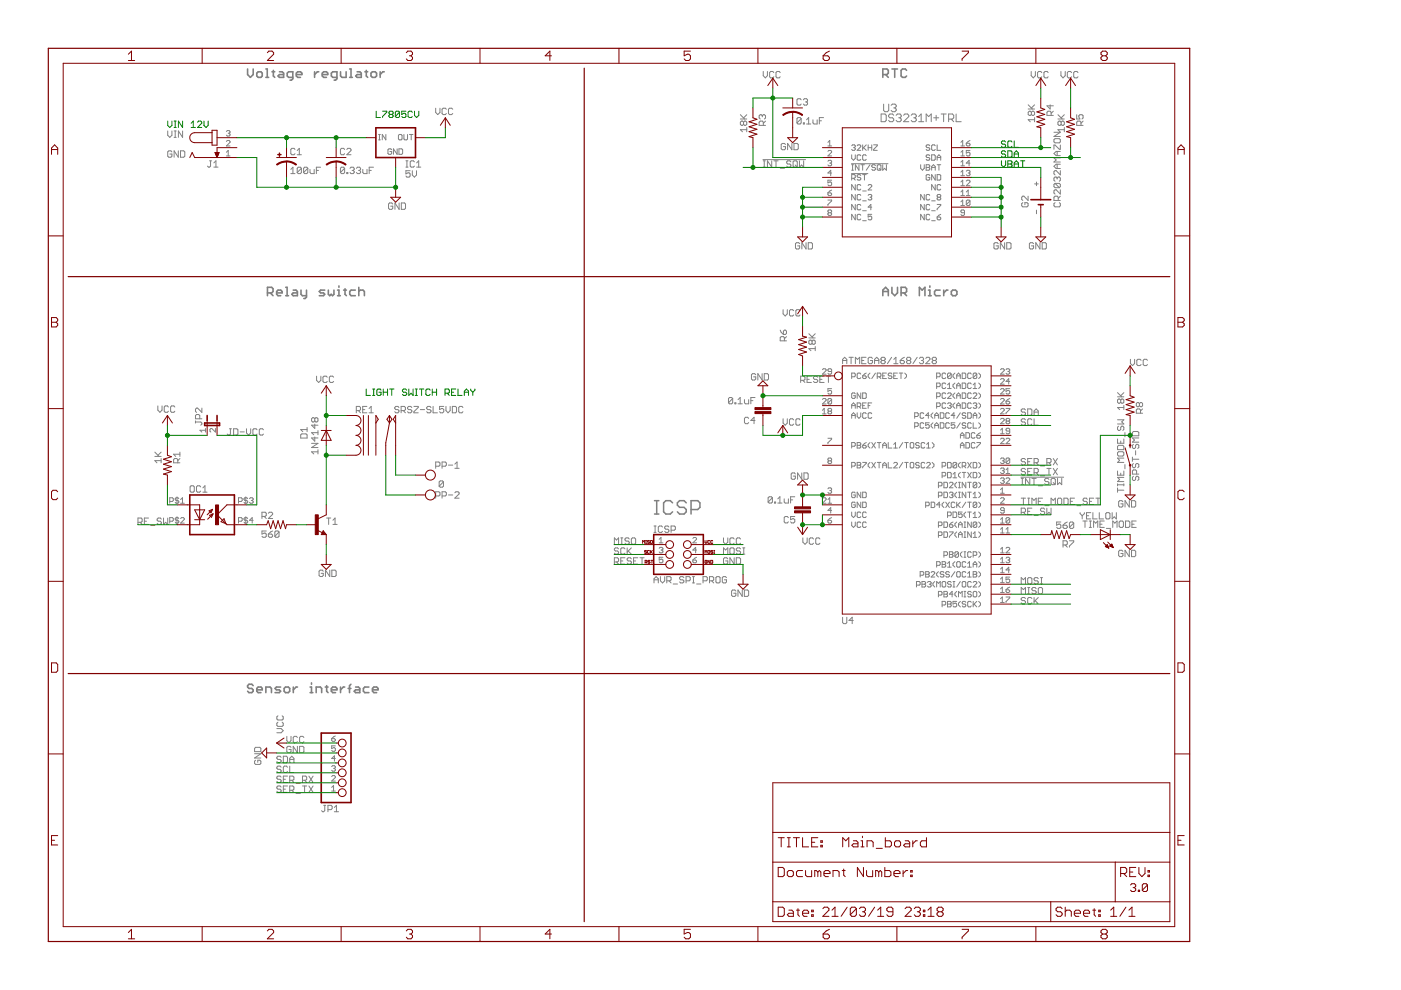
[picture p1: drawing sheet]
<svg xmlns="http://www.w3.org/2000/svg" width="297mm" height="210mm" viewBox="0 0 297 210" stroke-linecap="round" stroke-linejoin="round" font-family="sans-serif">
<g fill="none" stroke="#808080" stroke-width=".34">
<path d="M52.5 14.6v1.2l.6 .6 .6-.6v-1.2M54.4 15.5l.3-.3h.6l.3 .3v.6l-.3 .3h-.6l-.3-.3zM56.4 14.6h.3v1.8M56.4 16.4h.6M57.7 15.2h.6M58 14.9v1.2l.3 .3M59.2 15.2h.6l.3 .3v.9h-.9l-.3-.3 .3-.3h.9M62.1 16.4h-.9l-.3-.3v-.6l.3-.3h.9v1.5l-.3 .3h-.3M62.8 15.8h1.2v-.3l-.3-.3h-.6l-.3 .3v.6l.3 .3h.6M66.7 15.2v1.2M67.6 15.2h-.3l-.6 .6M68.3 15.8h1.2v-.3l-.3-.3h-.6l-.3 .3v.6l.3 .3h.6"/>
<path d="M71.4 16.4h-.9l-.2-.3v-.6l.2-.3h.9v1.5l-.3 .3h-.3M72.2 15.2v.9l.3 .3h.9v-1.2M74.1 14.6h.3v1.8M74.1 16.4h.6M75.7 15.2h.6l.3 .3v.9h-.9l-.3-.3 .3-.3h.9M77.4 15.2h.6M77.7 14.9v1.2l.3 .3M78.7 15.5l.3-.3h.5l.3 .3v.6l-.3 .3h-.5l-.3-.3zM80.6 15.2v1.2M81.5 15.2h-.3l-.6 .6M187.2 15.8h.8l.3-.3v-.6l-.3-.3h-.8v1.8M187.8 15.8l.5 .6"/>
<path d="M189.1 14.6h1.2M189.7 14.6v1.8M192.2 14.9l-.3-.3h-.6l-.2 .3v1.2l.2 .3h.6l.3-.3M56.7 62.1h.9l.3-.3v-.6l-.3-.3h-.9v1.8M57.3 62.1l.6 .6M58.7 62.1h1.1v-.3l-.3-.3h-.6l-.2 .3v.6l.2 .3h.6M60.6 60.9h.3v1.8M60.6 62.7h.6M62.2 61.5h.6l.3 .3v.9h-.9l-.3-.3 .3-.3h.9M63.8 61.5v.9l.3 .3h.9M65 61.5v1.5l-.3 .3h-.3M68.9 61.5h-.9l-.3 .3 .3 .3h.6l.3 .3-.3 .3h-.9"/>
<path d="M69.6 61.5v.9l.3 .3 .3-.3 .3 .3 .3-.3v-.9M71.6 61.5h.3v1.2M71.6 62.7h.6M71.9 60.6v.3M72.9 61.5h.5M73.2 61.2v1.2l.2 .3M75.3 61.5h-.9l-.3 .3v.6l.3 .3h.9M76.1 61.8l.3-.3h.6l.3 .3v.9M76.1 60.9v1.8M187.2 62.7v-1.2l.6-.6 .5 .6v1.2M187.2 61.8h1.1M189.1 60.9v1.2l.6 .6 .6-.6v-1.2"/>
<path d="M191.1 62.1h.8l.3-.3v-.6l-.3-.3h-.8v1.8M191.6 62.1l.6 .6M194.9 62.7v-1.8l.6 .6 .6-.6v1.8M196.8 61.5h.3v1.2M196.8 62.7h.6M197.1 60.6v.3M199.3 61.5h-.9l-.3 .3v.6l.3 .3h.9M200.1 61.5v1.2M201 61.5h-.3l-.6 .6M202 61.5h.6l.3 .3v.6l-.3 .3h-.6l-.3-.3v-.6zM53.7 145.4l-.3-.3h-.6l-.3 .3v.3l.3 .3h.6l.3 .3v.3l-.3 .3h-.6l-.3-.3M54.4 146.3h1.2v-.3l-.3-.3h-.6l-.3 .3v.6l.3 .3h.6"/>
<path d="M56.4 146.9v-1.2h.9l.3 .3v.9M59.5 145.7h-.9l-.3 .3 .3 .3h.6l.3 .3-.3 .3h-.9M60.2 146l.3-.3h.6l.3 .3v.6l-.3 .3h-.6l-.3-.3zM62.2 145.7v1.2M63.1 145.7h-.3l-.6 .6M65.7 146.9h.6M65.7 145.7h.3v1.2M66 144.8v.3M67 146.9v-1.2h.9l.3 .3v.9M69 145.7h.6M69.3 145.4v1.2l.3 .3M70.3 146.3h1.1v-.3l-.3-.3h-.6l-.2 .3v.6l.2 .3h.6"/>
<path d="M72.2 145.7v1.2M73.1 145.7h-.3l-.6 .6M73.8 146h.6M74.4 145.1l-.3 .3v1.5M75.4 145.7h.6l.3 .3v.9h-.9l-.3-.3 .3-.3h.9M78.2 145.7h-.9l-.3 .3v.6l.3 .3h.9M79 146.3h1.2v-.3l-.3-.3h-.6l-.3 .3v.6l.3 .3h.6"/>
</g>
<path d="M138.8 109h.9M138.8 106.2h.9M139.2 106.2v2.8M142.6 106.6l-.5-.4h-.9l-.5 .4v1.9l.5 .5h.9l.5-.5M145.5 106.6l-.5-.4h-.9l-.5 .4v.5l.5 .5h.9l.5 .4v.5l-.5 .5h-.9l-.5-.5M146.5 108h1.4l.5-.4v-1l-.5-.4h-1.4v2.8" fill="none" stroke="#808080" stroke-width=".32"/>
<g fill="none" stroke="#808080" stroke-width=".21">
<path d="M161.8 15.2v.8l.5 .5 .4-.5v-.8M164.1 15.4l-.2-.2h-.5l-.2 .2v.9l.2 .2h.5l.2-.2M165.4 15.4l-.2-.2h-.5l-.2 .2v.9l.2 .2h.5l.2-.2M218.6 15.2v.8l.5 .5 .4-.5v-.8M220.9 15.4l-.2-.2h-.5l-.2 .2v.9l.2 .2h.5l.2-.2M222.2 15.4l-.2-.2h-.4l-.3 .2v.9l.3 .2h.4l.2-.2M224.9 15.2v.8l.5 .5 .4-.5v-.8M227.2 15.4l-.2-.2h-.5l-.2 .2v.9l.2 .2h.5l.2-.2M228.6 15.4l-.3-.2h-.4l-.3 .2v.9l.3 .2h.4l.3-.2M35.6 27.8v.9l.4 .4 .4-.4v-.9M36.4 32.2l-.2-.2h-.4l-.2 .2v.9l.2 .2h.4l.2-.2v-.4h-.4M36.9 29.1h.5"/>
<path d="M36.9 27.8h.5M37.1 27.8v1.3M37.8 32v1.3l-.9-1.3v1.3M38.3 32h.6l.3 .2v.9l-.3 .2h-.6zM38.7 27.8v1.3l-.9-1.3v1.3M44.4 34.1h.5M44.6 34.1v1.1l-.2 .2-.4-.2M45.3 35.4h.9M45.3 34.5l.5-.4v1.3M48 30l.2-.2h.4l.2 .2v.2l-.8 .7h.8M48 33.1h.8M48 27.9l.2-.2h.4l.2 .2-.2 .4"/>
<path d="M48 32.3l.4-.4v1.2M48.4 28.3h.2M48.6 28.3l.2 .1-.2 .5h-.4l-.2-.2M61.7 36.8h.8M61.7 35.9l.4-.4v1.3M62.5 31.7l-.2-.2h-.4l-.2 .2v.9l.2 .2h.4l.2-.2M63 32.8h.9M63 31.9l.5-.4v1.3M63.9 35.7l-.2-.2h-.5l-.2 .2v.9M63.9 35.7v.9l-.2 .2h-.5l-.2-.2M63.9 35.7l-.9 .9M65.3 35.7l-.3-.2h-.4l-.2 .2v.9"/>
<path d="M65.3 35.7v.9l-.3 .2h-.4l-.2-.2M65.3 35.7l-.9 .9M65.7 35.9v.7l.3 .2h.6v-.9M67.1 36.1h.4M68 35.5h-.9v1.3M73.1 31.7l-.2-.2h-.5l-.2 .2v.9l.2 .2h.5l.2-.2M73.1 35.7l-.2-.2h-.5l-.2 .2v.9M73.1 35.7v.9l-.2 .2h-.5l-.2-.2M73.1 35.7l-.9 .9M73.5 36.6h.2v.2h-.2zM73.5 31.7l.2-.2h.5l.2 .2v.2l-.9 .9h.9M74.2 35.7l.2-.2h.5l.2 .2-.2 .4"/>
<path d="M74.7 36.1h.2M74.9 36.1l.2 .3-.2 .4h-.5l-.2-.2M75.6 35.7l.2-.2h.4l.3 .2-.3 .4M76 36.1h.2M76.2 36.1l.3 .3-.3 .4h-.4l-.2-.2M76.9 35.9v.7l.3 .2h.6v-.9M78.3 36.1h.4M79.2 35.5h-.9v1.3M80.3 29.7h.3M80.3 28.5h.3M80.5 28.5v1.2M81.8 28.5v1.2l-.8-1.2v1.2"/>
<path d="M83 31.7l-.2-.1h-.3l-.2 .1v.8l.2 .2h.3l.2-.2v-.4h-.3M84.2 31.6v1.1l-.8-1.1v1.1M84.6 31.6h.6l.2 .1v.8l-.2 .2h-.6zM84.7 28.5h.3l.2 .2v.8l-.2 .2h-.3l-.2-.2v-.8zM85.6 28.5v1l.2 .2h.4l.2-.2v-1M86.1 35.4h.4M86.1 34.1h.4M86.3 34.1v1.3M86.8 28.5h.8M87 36.2h-.9v.7l.4-.3h.2l.3 .3v.4l-.3 .2h-.4l-.2-.2M87.2 28.5v1.2M87.4 36.2v.9l.5 .4 .4-.4v-.9"/>
<path d="M87.9 34.3l-.3-.2h-.4l-.2 .2v.9l.2 .2h.4l.3-.2M88.3 35.4h.9M88.3 34.5l.5-.4v1.3M92.4 22.9v.9l.4 .5 .5-.5v-.9M94.6 23.2l-.2-.3h-.4l-.3 .3v.9l.3 .2h.4l.2-.2M96 23.2l-.2-.3h-.5l-.2 .3v.9l.2 .2h.5l.2-.2M157 25.2h1.3M157 24.3l.9 .9M157.6 25.9l-.2-.2-.4 .2v.5l.2 .2 .4-.2M157.6 25.9l.3-.2 .4 .2v.5l-.2 .2h-.2l-.3-.2M157.6 25.9v.5M158.3 27.5h-1.3l.4 .4"/>
<path d="M158.3 27v.9M158.3 24.3l-.7 .7M161.6 24.6v.2M161.6 24.6l-.2-.3-.4 .3v.4l.2 .2M161.6 24.6l.2-.3 .5 .3v.4l-.2 .2M161.8 33.8h9M161.8 35.4h.5M161.8 34.1h.5M161.8 26.6v-.7l-.2-.2h-.4l-.2 .2v.7h1.3M162 34.1v1.3M162.3 25.7l-.5 .4M163.6 34.1v1.3l-.9-1.3v1.3"/>
<path d="M164.1 34.1h.9M164.5 34.1v1.3M165.4 35.7h.9M166.5 30.6l-.2-.2h-.4l-.3 .2v.9l.3 .2h.4l.2-.2v-.4h-.4M167.7 34.3l-.2-.2h-.5l-.2 .2 .2 .5h.5l.2 .4-.2 .2h-.5l-.2-.2M167.9 30.4v1.3l-.9-1.3v1.3M168.1 34.3l.3-.2h.4l.2 .2v.9l-.2 .2h-.4l-.3-.2zM168.3 30.4h.7l.2 .2v.9l-.2 .2h-.7zM168.6 35l.4 .4M169.5 34.1v1.3l.4-.4 .5 .4v-1.3M169.9 21.2l-.2-.3h-.5l-.2 .3v.9l.2 .2h.5l.2-.2M169.9 25.2l-.2-.3h-.5l-.2 .3v.9"/>
<path d="M169.9 25.2v.9l-.2 .2h-.5l-.2-.2M169.9 25.2l-.9 .9M170.3 26.1h.2v.2h-.2zM170.3 21.2l.2-.3h.5l.2 .3-.2 .4M170.8 21.6h.2M171 25.4l.4-.5v1.4M171 26.3h.9M171 21.6l.2 .2-.2 .5h-.5l-.2-.2M172.4 25.4v.7l.2 .2h.6v-.9M173.7 25.6h.5M174.6 24.9h-.9v1.4M175.5 30.2l.4-.4v1.1"/>
<path d="M175.5 30.9h.8M175.5 34.2l.2-.2h.4l.2 .2-.2 .4M175.5 32.1l.2-.2h.4l.2 .2v.2l-.8 .8h.8M175.9 34.6h.2M176.1 34.6l.2 .2-.2 .4h-.4l-.2-.2M176.3 38.2h-.8v.6l.4-.2 .4 .2v.4l-.2 .2h-.4l-.2-.2M176.3 36.7h-.8l.6-.6v1.2M180.5 36.8h3.5M180.5 34.7h7.8M180.6 32.8v.8l.4 .4 .3-.4v-.8M180.6 30.9l.2-.2h.3l.2 .2-.2 .4M180.6 37.8h.5l.2-.2v-.4l-.2-.2h-.5v1.2"/>
<path d="M180.6 36.1h.4M180.6 34.9h.4M180.8 34.9v1.2M181 31.3h.1M181 37.8l.3 .4M181.1 31.3l.2 .2-.2 .4h-.3l-.2-.2M181.3 39.1v1.2l-.7-1.2v1.2M181.7 30.9l.2-.2h.4l.2 .2v.2l-.8 .8h.8M182.1 34.9v1.2l-.7-1.2v1.2M182.5 33l-.2-.2h-.4l-.2 .2v.8l.2 .2h.4l.2-.2M182.5 37.2l-.2-.2h-.4l-.2 .2 .2 .4h.4l.2 .2-.2 .4h-.4l-.2-.2M182.5 39.3l-.2-.2h-.4l-.2 .2v.8l.2 .2h.4l.2-.2"/>
<path d="M182.5 34.9h.8M182.9 30.7v1.2M182.9 34.9v1.2M182.9 37h.8M183.1 31.3l.6 .6M183.3 37v1.2M183.7 33l-.2-.2h-.4l-.2 .2v.8l.2 .2h.4l.2-.2M183.7 30.7l-.8 .8M184.1 30.7v1.2M184.1 31.3h.7M184.1 39.3l.2-.2h.3l.2 .2v.2l-.7 .8h.7M184.4 34.9l-.7 1.2"/>
<path d="M184.8 30.7v1.2M185.2 30.7h.8l-.8 1.2h.8M185.6 35.1l-.2-.2h-.4l-.2 .2 .2 .4h.4l.2 .2-.2 .4h-.4l-.2-.2M186 35.1l.2-.2h.4l.2 .2v.8l-.2 .2h-.4l-.2-.2zM186.4 35.7l.4 .4M186.8 24.2h.8l.3 .2v1.1l-.3 .3h-.8zM187.2 34.9v1.2l.3-.4 .4 .4v-1.2M187.3 22.1v1.3l.3 .3h.6l.2-.3v-1.3M188.9 22.3l.3-.2h.5l.3 .2v.3l-.3 .3M189.5 24.4l-.3-.2h-.5l-.3 .2v.3l.3 .3h.5l.3 .3v.2l-.3 .3h-.5l-.3-.3M189.5 22.9h.2M189.7 22.9l.3 .3v.2l-.3 .3h-.5l-.3-.3"/>
<path d="M190 24.4l.3-.2h.5l.3 .2v.3l-.3 .3M190.5 25h.3M190.8 25l.3 .3v.2l-.3 .3h-.5l-.3-.3M191.6 24.4l.3-.2h.5l.3 .2v.3l-1.1 1.1h1.1M193.2 24.4l.2-.2h.6l.3 .2v.3l-.3 .3M193.7 25h.3M194 25l.3 .3v.2l-.3 .3h-.6l-.2-.3M194.8 25.8h1.1M194.8 24.7l.5-.5v1.6M195.2 34.9v.8l.4 .4 .4-.4v-.8M196.4 25.8v-1.6l.5 .5 .5-.5v1.6M196.4 34.9h.5l.2 .2-.2 .4 .2 .4-.2 .2h-.5z"/>
<path d="M196.4 35.5h.5M197.1 30.9l-.2-.2h-.3l-.2 .2 .2 .4h.3l.2 .4-.2 .2h-.3l-.2-.2M197.1 33l-.2-.2h-.3l-.2 .4 .2 .2h.3l.2 .4-.2 .2h-.3l-.2-.2M197.1 37.2l-.2-.2h-.3l-.2 .2v.8l.2 .2h.3l.2-.2v-.4h-.4M197.5 32.8h.6l.2 .2v.8l-.2 .2h-.6zM197.5 35.5h.8M197.5 36.1v-.8l.4-.4 .4 .4v.8M198 25h1M198.3 30.9l-.2-.2h-.4l-.2 .2v.8l.2 .2h.4l.2-.2M198.3 37v1.2l-.8-1.2v1.2M198.3 39.1v1.2l-.8-1.2v1.2M198.5 24.4v1.1"/>
<path d="M198.7 30.7v1.2h.8M198.7 34.9h.8M198.7 37h.6l.2 .2v.8l-.2 .2h-.6zM198.7 34v-.8l.4-.4 .4 .4v.8M198.7 33.4h.8M199.1 34.9v1.2M199.5 39.3l-.2-.2h-.4l-.2 .2v.8l.2 .2h.4l.2-.2M199.5 24.2h1.1M200.1 24.2v1.6M201.1 25.3h.8l.3-.3v-.6l-.3-.2h-.8v1.6M201.7 25.3l.5 .5M202.7 24.2v1.6h1.1"/>
<path d="M203.7 30.9h.8M203.7 33.1h.8M203.7 35.2h.8M203.7 39.4h.8M203.7 30.2l.4-.4v1.1M203.7 32.3l.4-.4v1.2M203.7 34.4l.4-.4v1.2M203.7 36.5l.4-.4v1.2M203.7 38.6l.4-.4v1.2M203.7 37.3h.8M204.9 30.4h.6l.2 .4-.2 .1h-.4l-.2-.1zM204.9 36.3l.2-.2h.4l.2 .2-.2 .4"/>
<path d="M204.9 38.4l.2-.2h.4l.2 .2v.2l-.8 .8h.8M205.3 36.7h.2M205.5 36.7l.2 .2-.2 .4h-.4l-.2-.2M205.7 31.9h-.8v.6l.4-.2 .4 .2v.4l-.2 .2h-.4l-.2-.2M205.7 34.6h-.8l.6-.6v1.2M205.7 29.8l-.8 .6M218 23.1h1.4M218 22.2l.9 .9M218.7 23.8l.2-.2 .5 .2v.5l-.3 .2-.4-.2M218.7 23.8l-.3-.2-.4 .2v.5l.2 .2 .5-.2M218.7 23.8v.5M219.4 25.4h-1.4l.4 .4"/>
<path d="M219.4 24.9v.9M219.4 22.2l-.7 .7M219.4 39h.7M219.8 38.6v.8M222.7 22.2v.9l-.7-.7h1.3M222.9 24.5v-.7l-.2-.2h-.5l-.2 .2v.7h1.3M223.3 23.6l-.4 .4M223.5 29.6l.2-.2h.9l.2 .2v.5l-.2 .2h-.9l-.2-.2zM223.5 28h1.3l-1.3 .9h1.3M223.7 38.9l-.2 .2v.5l.2 .2h.9M223.7 38.9h.9l.2 .2v.5l-.2 .2M223.7 38.9l.9 .9"/>
<path d="M224.1 37.8l-.2-.3-.4 .3v.4l.2 .2M224.1 37.8l.3-.3h.2l.2 .3v.4l-.2 .2M224.1 32.1v.9M224.1 34.8v.9M224.1 37.8v.2M224.3 25.2h1.4M224.3 24.3l.9 .9M224.8 36.2v.9l-.9-.9-.4 .2v.5l.2 .2M224.8 30.8v.8h-.2l-.9-.8h-.2v.8M224.8 34.8h-.9l-.4 .5 .4 .4h.9M224.8 33.5h-1.3l.4 .4-.4 .5h1.3M224.8 32.1h-.9l-.4 .5 .4 .4h.9"/>
<path d="M225 25.9l.2-.2 .5 .2v.5l-.3 .2-.4-.2M225 25.9l-.3-.2-.4 .2v.5l.2 .2 .5-.2M225 25.9v.5M225.7 27.5h-1.4l.4 .4M225.7 27v.9M225.7 24.3l-.7 .7M228.3 24.3v.9h.7l-.3-.4 .3-.5h.4l.2 .3v.4l-.2 .2M229.2 26.6v-.7l-.2-.2h-.5l-.2 .2v.7h1.3M229.6 25.7l-.4 .4M83.3 43.3l-.2-.3h-.5l-.2 .3v.9l.2 .2h.5l.2-.2v-.5h-.5M84.6 43v1.4l-.9-1.4v1.4M85.1 43h.7l.2 .3v.9l-.2 .2h-.7z"/>
<path d="M169.5 51.7l-.2-.2h-.4l-.2 .2v.9l.2 .2h.4l.2-.2v-.5h-.4M170.9 51.5v1.3l-.9-1.3v1.3M171.4 51.5h.6l.3 .2v.9l-.3 .2h-.6zM175.5 40.9h.6l.2 .4-.2 .2h-.4l-.2-.2zM175.5 42.4h.8v.2l-.8 .8v.2M175.7 45.1l-.2-.2 .2-.4h.4l.2 .2-.2 .4M175.7 45.1l-.2 .2 .2 .4h.4l.2-.2-.2-.4M175.7 45.1h.4M176.3 40.3l-.8 .6M181.3 41.2v1.2l-.7-1.2v1.2M181.3 43.3v1.2l-.7-1.2v1.2M181.3 45.4v1.2l-.7-1.2v1.2"/>
<path d="M182.5 41.4l-.2-.2h-.4l-.2 .2v.8l.2 .2h.4l.2-.2M182.5 43.5l-.2-.2h-.4l-.2 .2v.8l.2 .2h.4l.2-.2M182.5 45.6l-.2-.2h-.4l-.2 .2v.8l.2 .2h.4l.2-.2M182.9 40.5h.8M182.9 42.6h.8M182.9 44.7h.8M182.9 46.8h.8M184.1 41.4l.2-.2h.3l.2 .2-.2 .4M184.4 41.8h.2M184.6 41.8l.2 .2-.2 .4h-.3l-.2-.2M184.8 45.4h-.7v.6l.3-.2 .4 .2v.4l-.2 .2h-.3l-.2-.2M184.8 43.9h-.7l.5-.6v1.2"/>
<path d="M196 41.2v1.2l-.8-1.2v1.2M196 43.3v1.2l-.8-1.2v1.2M196 45.4v1.2l-.8-1.2v1.2M197.1 41.4l-.2-.2h-.3l-.2 .2v.8l.2 .2h.3l.2-.2M197.1 43.5l-.2-.2h-.3l-.2 .2v.8l.2 .2h.3l.2-.2M197.1 45.6l-.2-.2h-.3l-.2 .2v.8l.2 .2h.3l.2-.2M197.5 42.6h.8M197.5 44.7h.8M197.5 46.8h.8M198.7 43.3h.8l-.8 1.2M198.7 46h.6l.2 .4-.2 .2h-.4l-.2-.2zM198.9 41.8l-.2 .2 .2 .4h.4l.2-.2-.2-.4"/>
<path d="M198.9 41.8l-.2-.2 .2-.4h.4l.2 .2-.2 .4M198.9 41.8h.4M199.5 45.4l-.8 .6M203.7 41.5h.8M203.7 42.8l.4-.4v1.2M203.7 40.7l.4-.4v1.2M203.7 43.6h.8M204.5 45.1h-.6l-.2-.2 .2-.4h.4l.2 .2v.8l-.2 .2h-.4l-.2-.2M204.9 41.5h.8M204.9 40.7l.4-.4v1.2M205.7 42.6l-.2-.2h-.4l-.2 .2v.8M205.7 42.6v.8l-.2 .2h-.4l-.2-.2"/>
<path d="M205.7 42.6l-.8 .8M211.6 51.7l-.2-.2h-.4l-.3 .2v.9l.3 .2h.4l.2-.2v-.5h-.4M213 51.5v1.3l-.9-1.3v1.3M213.4 51.5h.7l.3 .2v.9l-.3 .2h-.7zM216.9 43l-.3 .2v.4l.3 .3h.8l.3-.3v-.4l-.3-.2h-.4v.4M218 41.6v.9l-.9-.9-.5 .2v.5l.3 .2M219.1 51.7l-.2-.2h-.4l-.3 .2v.9l.3 .2h.4l.2-.2v-.5h-.4M219.8 44.6v.7M220.5 51.5v1.3l-.9-1.3v1.3M221 51.5h.6l.2 .2v.9l-.2 .2h-.6zM223.7 43l-.2 .2v.4l.2 .3h.9l.2-.3v-.4l-.2-.2M224.4 42.5v-.7l-.3-.2h-.4l-.2 .2v.7h1.3"/>
<path d="M224.8 40.2v.9l-.9-.9-.4 .3v.4l.2 .2M224.8 41.6l-.4 .5M67.1 79.8v.8l.5 .5 .4-.5v-.8M69.4 80l-.2-.2h-.5l-.2 .2v.9l.2 .2h.5l.2-.2M70.7 80l-.2-.2h-.4l-.3 .2v.9l.3 .2h.4l.2-.2M160.2 79.5l-.2-.3h-.4l-.3 .3v.8l.3 .3h.4l.2-.3v-.4h-.4M161.6 79.2v1.4l-.9-1.4v1.4M162 79.2h.7l.2 .3v.8l-.2 .3h-.7zM165.4 70l.2 .5 .5 .4M166 65.7v.8l.5 .5 .4-.5v-.8M166.3 72.3v-.7l-.2-.2h-.5l-.2 .2v.7h1.4M166.3 70h.2l.3 .2v.5l-.3 .2h-.4v-.7z"/>
<path d="M166.8 71.4l-.5 .4M168.3 65.9l-.3-.2h-.4l-.2 .2v.9l.2 .2h.4l.3-.2M169.6 65.9l-.2-.2h-.4l-.3 .2v.9l.3 .2h.4l.2-.2M171.5 71.6h1.3M171.5 70.8l.9 .8M172 79.8h-.9v1.3h.9M172.2 72.3l.2-.2 .4 .2v.5l-.2 .2-.4-.2M172.2 72.3l-.3-.2-.4 .2v.5l.2 .2 .5-.2M172.2 72.3v.5M172.8 73.9h-1.3l.4 .5M172.8 73.5v.9M172.8 70.8l-.6 .6"/>
<path d="M173.4 80l-.3-.2h-.4l-.2 .2 .2 .4h.4l.3 .2v.3l-.3 .2h-.4l-.2-.2M174.4 78.4l.2-.2h.4l.2 .2v.2l-.8 .7h.8M174.7 79.8h-.9v1.3h.9M175.2 79.8h.9M175.6 79.8v1.3M176.3 78.8h-.6l-.2-.2 .2-.4h.4l.2 .2v.7l-.2 .2h-.4l-.2-.2M178.6 77.1v-.9l.5-.4 .4 .4v.9M178.6 76.4h.9M180 75.8h.9M180.4 75.8v1.3M180.6 79.9h.5l.2-.2v-.4l-.2-.2h-.5v1.2M181.4 77.1v-1.3l.4 .4 .5-.4v1.3"/>
<path d="M182.5 79.3l-.2-.2h-.4l-.2 .2v.8l.2 .2h.4l.2-.2M182.7 76.4h.5M182.9 79.7h.6l.2 .4-.2 .2h-.4l-.2-.2zM183.6 75.8h-.9v1.3h.9M183.7 79.1l-.8 .6M184.4 79.1l-.3 .4v.4l.3 .4M185 76l-.3-.2h-.4l-.2 .2v.9l.2 .2h.4l.3-.2v-.5h-.5M185.4 76.4h.9M185.4 77.1v-.9l.5-.4 .4 .4v.9M185.6 79.1l-.8 1.2M186 79.9h.6l.2-.2v-.4l-.2-.2h-.6v1.2M186.4 79.9l.4 .4"/>
<path d="M187 76.4l-.2-.2 .2-.4h.5l.2 .2-.2 .4M187 76.4h.5M187 76.4l-.2 .2 .2 .5h.5l.2-.2v-.3l-.2-.2M187.2 79.7h.3M187.9 79.1h-.7v1.2h.7M189 75.8l-.8 1.3M189.1 79.3l-.2-.2h-.4l-.2 .4 .2 .2h.4l.2 .4-.2 .2h-.4l-.2-.2M189.5 79.7h.4M189.5 77.1h.9M189.5 76.2l.4-.4v1.3M190.3 79.1h-.8v1.2h.8M190.6 79.1h.8"/>
<path d="M190.9 76.4h.6l.2 .5-.2 .2h-.4l-.2-.2zM191 79.1v1.2M191.7 75.8l-.8 .6M191.8 79.1l.4 .4v.4l-.4 .4M192.4 76.4h.5M192.4 76.4l-.2-.2 .2-.4h.5l.2 .2-.2 .4M192.4 76.4l-.2 .2 .2 .5h.5l.2-.2-.2-.5M194.5 75.8l-.9 1.3M194.9 76l.3-.2h.4l.2 .2-.2 .4M195.4 76.4h.2M195.6 76.4l.2 .2-.2 .5h-.4l-.3-.2M196.3 76l.2-.2h.5l.2 .2v.2l-.9 .9h.9"/>
<path d="M197.9 76.4h.4M197.9 76.4l-.3-.2 .3-.4h.4l.2 .2-.2 .4M197.9 76.4l-.3 .2 .3 .5h.4l.2-.2v-.3l-.2-.2M198.6 79.9h.6l.1-.2v-.4l-.1-.2h-.6v1.2M200.5 79.3l-.2-.2h-.4l-.2 .2v.8l.2 .2h.4l.2-.2M201.7 79.3l-.2-.2h-.4l-.2 .2v.8M201.7 79.3v.8l-.2 .2h-.4l-.2-.2M201.7 79.3l-.8 .8M202.5 79.1l-.4 .4v.4l.4 .4M202.8 79.7h.8M204 79.1h.6l.2 .2v.8l-.2 .2h-.6zM205.9 79.3l-.2-.2h-.3l-.2 .2v.8l.2 .2h.3l.2-.2"/>
<path d="M207.1 79.3l-.2-.2h-.4l-.2 .2v.8M207.1 79.3v.8l-.2 .2h-.4l-.2-.2M207.1 79.3l-.8 .8M207.5 79.1l.4 .4v.4l-.4 .4M212.1 78.4l.2-.2h.4l.2 .2v.2l-.8 .7h.8M213.3 78.4l.2-.2h.4l.2 .2-.2 .4M213.7 78.8h.2M213.9 78.8l.2 .2-.2 .3h-.4l-.2-.2M239.7 76.2v.9l.4 .4 .5-.4v-.9M241.9 76.4l-.2-.2h-.4l-.3 .2v.9l.3 .2h.4l.2-.2M243.3 76.4l-.2-.2h-.5l-.2 .2v.9l.2 .2h.5l.2-.2M32.8 96.8h1.4"/>
<path d="M32.8 95.9l.9 .9M33.5 86.1v.9l.4 .4 .5-.4v-.9M34.2 97.7h-1.4l.5 .4M34.2 97.2v.9M34.2 95.9l-.7 .6M35.7 86.3l-.2-.2h-.5l-.2 .2v.9l.2 .2h.5l.2-.2M37.1 86.3l-.2-.2h-.5l-.2 .2v.9l.2 .2h.5l.2-.2M37.7 98.1v-.6l-.2-.3h-.5l-.2 .3v.6h1.3M38.1 97.2l-.4 .5M38.1 96.3h-1.3l.5 .5M38.1 95.9v.9M41.4 89.5h1.2l.2 .2-.2 .4"/>
<path d="M41.4 89.2v.5M42.4 88.8v-.7l-.3-.2h-.4l-.3 .2v.7h1.4M42.8 86.5v.9l-.9-.9-.5 .3v.4l.3 .2M43.6 91.2h-1.2l.4 .4M43.6 90.8v.8M45.7 90.8v.8l-.8-.8-.4 .2v.4l.2 .2M48.6 90.9h.5M48.9 90.9v1.1l-.3 .2-.4-.2M49.5 90.9h.7l.2 .2v.9l-.2 .2h-.7zM50.9 91.6h.9M52.3 90.9v.9l.4 .4 .4-.4v-.9M54.5 91.1l-.2-.2h-.5l-.2 .2v.9l.2 .2h.5l.2-.2"/>
<path d="M55.9 91.1l-.3-.2h-.4l-.2 .2v.9l.2 .2h.4l.3-.2M63.8 92.2l.2-.2h.9l.2 .2v.7h-1.3zM65.1 90.6v.9M65.1 91.1h-1.3l.4 .4M66.1 94h1.3l-1.3 .9h1.3M66.7 88.8l.3-.2 .4 .2v.4l-.2 .3-.5-.3M66.7 92.6v.9l-.6-.6h1.3M66.7 88.8v.4M66.7 89.9v.9l-.6-.7h1.3M66.7 88.8l-.2-.2-.4 .2v.4l.2 .3h.2l.2-.3M67.4 95.8h-1.3l.4 .4M67.4 91.3v.9"/>
<path d="M67.4 95.4v.8M67.4 91.7h-1.3l.4 .5M75.5 87.1h.7l.2-.3v-.4l-.2-.2h-.7v1.3M76 87.1l.4 .4M76.9 86.8h.4M77.8 86.2h-.9v1.3h.9M78.3 87.5h.8M78.3 86.6l.4-.4v1.3M84.6 86.4l-.2-.2h-.5l-.2 .2 .2 .4h.5l.2 .3-.2 .4h-.5l-.2-.2M85 87.1h.7l.3-.3v-.4l-.3-.2h-.7v1.3M85.5 87.1l.5 .4M87.3 86.4l-.2-.2h-.5l-.2 .4 .2 .2h.5l.2 .3v.2l-.2 .2h-.5l-.2-.2"/>
<path d="M87.8 86.2h.9v.2l-.9 .9v.2h.9M89.1 86.8h.9M91.4 86.4l-.3-.2h-.4l-.2 .4 .2 .2h.4l.3 .3v.2l-.3 .2h-.4l-.2-.2M91.8 86.2v1.3h.9M92.4 98.8h.6l.3-.2v-.4l-.3-.2h-.6v1.3M93.7 98.8h.7l.2-.2v-.4l-.2-.2h-.7v1.3M94.1 86.2h-.9v.6l.4-.2 .5 .2v.5l-.2 .2h-.5l-.2-.2M94.6 86.2v.9l.4 .4 .4-.4v-.9M95.1 98.6h.9M95.9 86.2h.7l.2 .2v.9l-.2 .2h-.7zM96.4 98.4l.5-.4v1.3M96.4 99.3h.9"/>
<path d="M98.1 86.4l-.2-.2h-.4l-.2 .2v.9l.2 .2h.4l.2-.2M155.3 84.5l-.2-.2h-.4l-.2 .2v.9M155.3 84.5v.9l-.2 .2h-.4l-.2-.2M155.3 84.5l-.8 .9M155.8 85.4h.2v.2h-.2zM156.5 84.7l.4-.4v1.3M156.5 85.6h.9M157.8 84.7v.7l.3 .2h.6v-.9M158.7 88.7l-.2-.2h-.4l-.3 .2v.9l.3 .2h.4l.2-.2M159.2 84.9h.4M160.1 84.3h-.9v1.3M160.1 89.2h-.9l.7-.7v1.3"/>
<path d="M166 88.8v.9l.5 .4 .4-.4v-.9M168.3 89l-.3-.2h-.4l-.2 .2v.9l.2 .2h.4l.3-.2M169.6 89l-.2-.2h-.4l-.3 .2v.9l.3 .2h.4l.2-.2M169.8 80.6h.6l.3-.2v-.4l-.3-.2h-.6v1.3M170.2 80.6l.5 .5M171.1 80.4h.5M173.8 80.4h.5M174.4 84.7l.2-.2h.4l.2 .2v.2l-.8 .8h.8M174.4 87l.4-.4v1.2M174.4 87.8h.8M175.5 92.9h.8v.2l-.8 .8v.2M175.7 97.7h.4"/>
<path d="M175.7 87.2l-.2-.2 .2-.4h.4l.2 .2-.2 .4M175.7 97.7l-.2 .2 .2 .4h.4l.2-.2-.2-.4M175.7 87.2l-.2 .2 .2 .4h.4l.2-.2-.2-.4M175.7 97.7l-.2-.2 .2-.4h.4l.2 .2-.2 .4M175.7 87.2h.4M176.3 82.4h-.8v.6l.4-.2 .4 .2v.4l-.2 .1h-.4l-.2-.1M176.3 84.7v.8l-.2 .2h-.4l-.2-.2M176.3 84.7l-.2-.2h-.4l-.2 .2v.8M176.3 84.7l-.8 .8M180.6 86.6v-.8l.4-.4 .3 .4v.8M180.6 88.7v-.8l.4-.4 .3 .4v.8M180.6 94.6h.5l.2-.2v-.4l-.2-.2h-.5v1.2"/>
<path d="M180.6 98.8h.5l.2-.2v-.4l-.2-.2h-.5v1.2M180.6 86h.7M180.6 88.1h.7M181.3 83.5l-.2-.2h-.3l-.2 .2v.8l.2 .2h.3l.2-.2v-.4h-.3M181.7 86.2h.6l.2-.2v-.4l-.2-.2h-.6v1.2M181.7 98.6h.6M181.7 87.5v.8l.4 .4 .4-.4v-.8M181.7 93.8h.6l.2 .2-.2 .4 .2 .4-.2 .2h-.6zM181.7 98h.6l.2 .2-.2 .4 .2 .4-.2 .2h-.6zM181.7 94.4h.6M182.1 86.2l.4 .4M182.5 83.3v1.2l-.8-1.2v1.2"/>
<path d="M182.9 83.3h.6l.2 .2v.8l-.2 .2h-.6zM182.9 94.4h.6l.2 .4-.2 .2h-.4l-.2-.2zM182.9 98h.8l-.8 1.2M182.9 86h.4M183.7 87.7l-.2-.2h-.4l-.2 .2v.8l.2 .2h.4l.2-.2M183.7 85.4h-.8v1.2h.8M183.7 93.8l-.8 .6M184.1 86h.3M184.4 93.8l-.3 .4v.4l.3 .4M184.4 98l-.3 .4v.4l.3 .4M184.8 87.7l-.2-.2h-.3l-.2 .2v.8l.2 .2h.3l.2-.2M184.8 85.4h-.7v1.2"/>
<path d="M184.8 98l.8 1.2M184.8 93.8l.8 1.2M185.6 98l-.8 1.2M185.6 93.8l-.8 1.2M186 98h.8M186 93.8h.8M186.4 93.8v1.2M186.4 98v1.2M187.2 98.6h.7M187.2 95v-.8l.3-.4 .4 .4v.8M187.2 99.2v-.8l.3-.4 .4 .4v.8M187.2 94.4h.7"/>
<path d="M188.3 98v1.2h.8M188.3 93.8v1.2h.8M189.5 98.2l.2-.2h.4l.2 .2v.2l-.8 .8h.8M189.5 95h.8M189.5 94.2l.4-.4v1.2M191.4 98l-.8 1.2M191.4 93.8l-.8 1.2M191.8 98h.8M191.8 93.8h.8M192.2 93.8v1.2M192.2 98v1.2M193 94l.2-.2h.3l.2 .2v.8l-.2 .2h-.3l-.2-.2z"/>
<path d="M193.2 98h.3l.2 .2v.8l-.2 .2h-.3l-.2-.2v-.8zM193.9 88.3h.6l.2-.2v-.4l-.2-.2h-.6v1.2M193.9 90.4h.6l.2-.2v-.4l-.2-.2h-.6v1.2M194.9 98.2l-.2-.2h-.4l-.2 .2 .2 .4h.4l.2 .2-.2 .4h-.4l-.2-.2M194.9 94l-.2-.2h-.4l-.2 .2 .2 .4h.4l.2 .2-.2 .4h-.4l-.2-.2M195.9 87.7l-.2-.2h-.4l-.2 .2v.8l.2 .2h.4l.2-.2M195.9 89.8l-.2-.2h-.4l-.2 .2v.8l.2 .2h.4l.2-.2M196.1 94l-.2-.2h-.4l-.2 .2v.8l.2 .2h.4l.2-.2M196.1 98.2l-.2-.2h-.4l-.2 .2v.8l.2 .2h.4l.2-.2M196.5 98.2l.2-.2h.3l.2 .2v.2l-.7 .8h.7M196.5 95h.7M196.5 94.2l.3-.4v1.2"/>
<path d="M197 89.6h-.7v.6l.3-.2 .4 .2v.4l-.2 .2h-.4l-.1-.2M197 88.1h-.7l.5-.6v1.2M197.6 98l.4 .4v.4l-.4 .4M197.6 93.8l.4 .4v.4l-.4 .4M197.8 87.5l-.4 .4v.4l.4 .4M197.8 89.6l-.4 .4v.4l.4 .4M198.2 88.1h.8M198.2 88.7v-.8l.4-.4 .4 .4v.8M198.2 90.8v-.8l.4-.4 .4 .4v.8M198.2 90.2h.8M198.6 86.2h.6l.1-.2v-.4l-.1-.2h-.6v1.2M198.6 82h.6l.1-.2v-.4l-.1-.2h-.6v1.2"/>
<path d="M198.6 84.1h.6l.1-.2v-.4l-.1-.2h-.6v1.2M199.3 87.5h.6l.2 .2v.8l-.2 .2h-.6zM199.3 89.6h.6l.2 .2v.8l-.2 .2h-.6zM199.7 98.8h.6l.2-.2v-.4l-.2-.2h-.6v1.2M200.5 85.6l-.2-.2h-.4l-.2 .2v.8l.2 .2h.4l.2-.2M200.5 81.4l-.2-.2h-.4l-.2 .2v.8l.2 .2h.4l.2-.2M200.5 83.5l-.2-.2h-.4l-.2 .2v.8l.2 .2h.4l.2-.2M200.9 98h.6l.2 .2v.8l-.2 .2h-.6zM200.9 83.5l.2-.2h.4l.2 .2v.2l-.8 .8h.8M200.9 85.6l.2-.2h.4l.2 .2-.2 .4M200.9 81.6l.4-.4v1.2M200.9 82.4h.8"/>
<path d="M201.3 87.7l-.2-.2h-.4l-.2 .2v.8l.2 .2h.4l.2-.2M201.3 89.8l-.2-.2h-.4l-.2 .2v.8l.2 .2h.4l.2-.2M201.3 86h.2M201.5 86l.2 .2-.2 .4h-.4l-.2-.2M202.5 89.6h-.8v.6l.4-.2 .4 .2v.4l-.3 .2h-.3l-.2-.2M202.5 81.2l-.4 .4v.4l.4 .4M202.5 83.3l-.4 .4v.4l.4 .4M202.5 85.4l-.4 .4v.4l.4 .4M202.5 88.1h-.8l.5-.6v1.2M202.8 98.2l-.2-.2h-.4l-.1 .2v.8M202.8 80.3v-.8l.4-.4 .4 .4v.8M202.8 82.4v-.8l.4-.4 .4 .4v.8"/>
<path d="M202.8 84.5v-.8l.4-.4 .4 .4v.8M202.8 86.6v-.8l.4-.4 .4 .4v.8M202.8 98.2v.8l-.2 .2h-.4l-.1-.2M202.8 83.9h.8M202.8 86h.8M202.8 98.2l-.7 .8M202.8 81.8h.8M203.6 89.6l-.8 1.2M203.6 87.5l-.8 1.2M203.6 98l-.4 .4v.4l.4 .4M203.6 94.4h.8M203.6 92.9v-.8l.4-.4 .4 .4v.8"/>
<path d="M203.6 95v-.8l.4-.4 .4 .4v.8M203.6 92.3h.8M204 83.3h.6l.2 .2v.8l-.2 .2h-.6zM204 81.2h.6l.2 .2v.8l-.2 .2h-.6zM204 85.4h.6l.2 .2v.8l-.2 .2h-.6zM204 98.8h.6l.2-.2v-.4l-.2-.2h-.6v1.2M204.4 98.8l.4 .4M204.8 87.7l-.2-.2h-.4l-.2 .2 .2 .4h.4l.2 .2-.2 .4h-.4l-.2-.2M204.8 89.8l-.2-.2h-.4l-.2 .4 .2 .2h.4l.2 .4-.2 .2h-.4l-.2-.2M204.8 91.7h.6l.1 .2v.8l-.1 .2h-.6zM204.8 93.8h.6l.1 .2v.8l-.1 .2h-.6zM205.2 87.5h.5l.2 .2v.8l-.2 .2h-.5z"/>
<path d="M205.2 98l.7 1.2M205.9 81.4l-.2-.2h-.3l-.2 .2v.8l.2 .2h.3l.2-.2M205.9 83.5l-.2-.2h-.3l-.2 .2v.8l.2 .2h.3l.2-.2M205.9 85.6l-.2-.2h-.3l-.2 .2v.8l.2 .2h.3l.2-.2M205.9 89.8l-.2-.2h-.3l-.2 .2v.8l.2 .2h.3l.2-.2M205.9 98l-.7 1.2M206.3 88.7v-.8l.4-.4 .4 .4v.8M206.3 85.6l.2-.2h.4l.2 .2-.2 .4M206.3 89.6v1.2h.8M206.3 98h.6l.2 .2v.8l-.2 .2h-.6zM206.3 83.5l.2-.2h.4l.2 .2v.2l-.8 .8h.8M206.3 88.1h.8"/>
<path d="M206.3 81.6l.4-.4v1.2M206.3 82.4h.8M206.7 91.9l-.2-.2h-.4l-.2 .2v.8l.2 .2h.4l.2-.2M206.7 94l-.2-.2h-.4l-.2 .2v.8l.2 .2h.4l.2-.2M206.7 86h.2M206.9 86l.2 .2-.2 .4h-.4l-.2-.2M207.1 92.3h.6l.2 .4-.2 .2h-.4l-.2-.2zM207.1 93.8h.8v.2l-.8 .8v.2M207.5 81.2l.4 .4v.4l-.4 .4M207.5 83.3l.4 .4v.4l-.4 .4M207.5 85.4l.4 .4v.4l-.4 .4M207.5 87.5l.4 .4v.4l-.4 .4"/>
<path d="M207.5 89.6l.4 .4v.4l-.4 .4M207.5 98l.4 .4v.4l-.4 .4M207.9 91.7l-.8 .6M212.1 86.8l.2-.2h.4l.2 .2v.2l-.8 .8h.8M212.1 91.2l.4-.4v1.2M212.1 99.4l.2-.2h.4l.2 .2-.2 .4M212.1 82.6l.2-.2h.4l.2 .2v.2l-.8 .7h.8M212.1 84.7l.2-.2h.4l.2 .2v.2l-.8 .8h.8M212.1 97.3l.2-.2h.4l.2 .2-.2 .4M212.1 80.5l.2-.2h.4l.2 .2v.2l-.8 .7h.8M212.1 93.1l.2-.2h.4l.2 .2v.2l-.8 .8h.8M212.1 88.9l.2-.2h.4l.2 .2v.2l-.8 .8h.8"/>
<path d="M212.1 92h.8M212.5 97.7h.2M212.5 99.8h.2M212.7 97.7l.2 .2-.2 .4h-.4l-.2-.2M212.7 99.8l.2 .2-.2 .4h-.4l-.2-.2M213.3 86.6h.8v.2l-.8 .8v.2M213.3 85.1h.6l.2 .4-.2 .2h-.4l-.2-.2zM213.3 93.1l.2-.2h.4l.2 .2v.2l-.8 .8h.8M213.3 99.6l.4-.4v1.2M213.5 89.3l-.2-.2 .2-.4h.4l.2 .2-.2 .4M213.5 89.3l-.2 .2 .2 .4h.4l.2-.2-.2-.4M213.5 89.3h.4"/>
<path d="M214.1 97.3v.8l-.2 .2h-.4l-.2-.2M214.1 91.4h-.6l-.2-.2 .2-.4h.4l.2 .2v.8l-.2 .2h-.4l-.2-.2M214.1 82.4h-.8v.6l.4-.2 .4 .2v.4l-.2 .1h-.4l-.2-.1M214.1 97.3l-.2-.2h-.4l-.2 .2v.8M214.1 80.9h-.8l.6-.6v1.1M214.1 97.3l-.8 .8M214.1 84.5l-.8 .6M217.4 89l-.2-.2h-.5l-.2 .4 .2 .3h.5l.2 .4-.2 .2h-.5l-.2-.2M217.4 97.4l-.2-.2h-.5l-.2 .2 .2 .5h.5l.2 .2-.2 .5h-.5l-.2-.3M217.4 99.5l-.2-.2h-.5l-.2 .2 .2 .5h.5l.2 .2-.2 .5h-.5l-.2-.3M217.4 86.9l-.2-.2h-.5l-.2 .2 .2 .5h.5l.2 .2-.2 .5h-.5l-.2-.3M217.9 86.7h.6l.3 .2v.9l-.3 .3h-.6z"/>
<path d="M217.9 97.9h.4M217.9 100h.4M218.8 89l-.3-.2h-.4l-.2 .2v.9l.2 .2h.4l.3-.2M218.8 97.2h-.9v1.4h.9M218.8 99.3h-.9v1.4h.9M219.2 88.8v1.3h.9M219.2 98.1h.7l.2-.2v-.5l-.2-.2h-.7v1.4M219.2 88.1v-1l.5-.4 .4 .4v1M219.2 87.4h.9M219.7 98.1l.4 .5M220.6 98.8h.9M222 98.1h.6l.2-.2v-.5l-.2-.2h-.6v1.4"/>
<path d="M222 99.3h.8M222.4 99.3v1.4M222.4 98.1l.4 .5M223.3 97.2l.9 1.4M223.3 99.3l.9 1.4M224.2 97.2l-.9 1.4M224.2 99.3l-.9 1.4M236.9 93.1v.9h1.4v-.9M236.9 99.9v.9h1.4v-.9M236.9 84.1h1.4M236.9 83.2l.9 .9M236.9 89h1.4l-.5 .5 .5 .4h-1.4"/>
<path d="M237.2 95.8h.9l.2 .2v.5l-.2 .2h-.9l-.3-.2v-.5zM237.2 90.4l-.3 .2v.4l.3 .3 .4-.3v-.4l.2-.2h.3l.2 .2v.4l-.2 .3M237.2 94.4h.9l.2 .3v.6h-1.4v-.6zM237.6 84.8l.2-.2 .5 .2v.5l-.2 .2-.5-.2M237.6 84.8l-.2-.2-.5 .2v.5l.3 .2 .4-.2M237.6 84.8v.5M237.6 93.5v.5M238.3 86.4h-1.4l.5 .4M238.3 86v.8M238.3 83.2l-.7 .7M238.3 97.1h-1.4l.5 .5-.5 .4h1.4M238.5 91.7v.9"/>
<path d="M238.5 98.5v.9M240.1 96.9v.9M240.1 97.4h1.3M240.3 98.3l-.2 .2v.5l.2 .2 .5-.2v-.5l.2-.2 .4 .2v.5l-.2 .2M240.3 91.5h.9l.2 .2v.7h-1.3v-.7zM240.3 94.2l-.2 .2v.5l.2 .2 .5-.2v-.5l.2-.2 .4 .2v.5l-.2 .2M240.8 95.6v.9M241.4 92.9h-1.3l.4 .4-.4 .4h1.3M241.6 85.6l-.2-.3h-.3l-.2 .3v.4l.2 .2 .5-.2M241.6 85.6l.2-.3h.2l.3 .3v.4l-.3 .2-.4-.2M241.6 85.6v.4M241.8 87.6v-.7l-.2-.2h-.5l-.2 .2v.7h1.4"/>
<path d="M242.3 86.7l-.5 .4M29.3 110.7h.6l.2-.2v-.4l-.2-.3h-.6v1.4M29.7 110.7l.4 .5M30.6 110.5h.5M31.5 109.8h-.9v1.4h.9M32 111.4h.9M34.2 110.1l-.2-.3h-.5l-.2 .3v.2l.2 .2h.5l.2 .2-.2 .5h-.5l-.2-.2M34.7 109.8v1.4l.4-.5 .5 .5v-1.4M36 106.3h.6l.1-.2v-.4l-.1-.2h-.6v1.2M36 110.5h.6l.1-.2v-.4l-.1-.2h-.6v1.2M37.5 105.3v1.6M37.5 109.6v1.5"/>
<path d="M37.9 105.7l-.2-.2h-.4l-.2 .2 .2 .4h.4l.2 .2-.2 .4h-.4l-.2-.2M37.9 109.9l-.2-.2h-.4l-.2 .2 .2 .4h.4l.2 .2-.2 .4h-.4l-.2-.2M38.3 106.7h.8M38.3 109.9l.2-.2h.4l.2 .2v.2l-.8 .8h.8M38.3 105.9l.4-.4v1.2M40.5 103h.5l.2 .2v.9l-.2 .3h-.5l-.2-.3v-.9zM42.5 103.2l-.2-.2h-.4l-.2 .2v.9l.2 .3h.4l.2-.3M43 104.4h.9M43 103.4l.5-.4v1.4M50.6 106.3h.6l.2-.2v-.4l-.2-.2h-.6v1.2M50.6 110.5h.6l.2-.2v-.4l-.2-.2h-.6v1.2M52.1 105.3v1.6"/>
<path d="M52.1 109.6v1.5M52.5 105.7l-.2-.2h-.4l-.2 .4 .2 .2h.4l.2 .4-.2 .2h-.4l-.2-.2M52.5 109.9l-.2-.2h-.4l-.2 .2 .2 .4h.4l.2 .2-.2 .4h-.4l-.2-.2M52.9 105.7l.2-.2h.4l.2 .2-.2 .4M53.3 106.1h.2M53.5 106.1l.2 .2-.2 .4h-.4l-.2-.2M53.7 110.3h-.8l.6-.6v1.2M55.5 109.5h.7l.3-.2v-.5l-.3-.2h-.7v1.3M56 109.5l.5 .4M56.5 112.6h-1v.6l.5-.2 .5 .2v.5l-.3 .2h-.4l-.3-.2M56.9 113.2h.7l.2 .5-.2 .2h-.5l-.2-.2zM56.9 108.8l.2-.2h.5l.2 .2v.3l-.9 .8h.9"/>
<path d="M57.8 112.6l-.9 .6M59.2 112.8l-.3-.2h-.4l-.2 .2v.9M59.2 112.8v.9l-.3 .2h-.4l-.2-.2M59.2 112.8l-.9 .9M69.2 109.8h.9M69.7 109.8v1.4M70.6 110.3l.4-.5v1.4M70.6 111.2h.9M92.4 105.2h.6l.3-.3v-.4l-.3-.2h-.6v1.3M93.7 105.2h.7l.2-.3v-.4l-.2-.2h-.7v1.3M94 102.2l-.2-.2h-.5l-.2 .2v.9M94 102.2v.9l-.2 .2h-.5l-.2-.2"/>
<path d="M94 102.2l-.9 .9M95.1 104.9h.9M96.4 104.5l.3-.2h.4l.2 .2v.2l-.9 .9h.9M130.3 119.1h.6l.2-.2v-.4l-.2-.2h-.6v1.3M130.3 115.4v-1.4l.4 .5 .4-.5v1.4M130.7 119.1l.4 .5M131.1 116.4l-.2-.2h-.4l-.2 .2 .2 .4h.4l.2 .3v.2l-.2 .2h-.4l-.2-.2M131.6 114h.5M131.6 115.4h.5M131.6 118.9h.5M131.8 114v1.4M132.5 118.3h-.9v1.3h.9"/>
<path d="M132.5 116.4l-.2-.2h-.5l-.2 .2v.9l.2 .2h.5l.2-.2M133 116.2v1.3M133.2 116.8l.7 .7M133.4 114.3l-.2-.3h-.5l-.2 .3 .2 .4h.5l.2 .3-.2 .4h-.5l-.2-.2M133.9 116.2l-.9 .9M133.9 118.5l-.3-.2h-.4l-.2 .2 .2 .4h.4l.3 .2-.3 .5h-.4l-.2-.2M134.1 114h.4l.3 .3v.9l-.3 .2h-.4l-.2-.2v-.9zM134.3 118.9h.5M135.2 118.3h-.9v1.3h.9M135.7 118.3h.9M136.1 118.3v1.3M138.7 112.9h.4"/>
<path d="M138.7 111.5h.4M138.9 111.5v1.4M139.8 116.2l.2-.1h.3l.2 .1-.2 .4M139.8 114.3l.3-.3v1.1M139.8 115.1h.7M140.1 116.6h.2M140.3 116.6l.2 .2-.2 .4h-.3l-.2-.2M140.5 111.7l-.2-.2h-.5l-.2 .2v.9l.2 .3h.5l.2-.3M140.5 118.2h-.7v.5l.3-.1 .4 .1v.4l-.2 .2h-.3l-.2-.2M141.8 111.7l-.2-.2h-.4l-.3 .2 .3 .5h.4l.2 .2-.2 .5h-.4l-.3-.3M142.3 112.4h.7l.2-.2v-.5l-.2-.2h-.7v1.4M146.9 118.7h.6l.2 .4-.2 .2h-.4l-.2-.2z"/>
<path d="M146.9 114.2l.2-.2h.4l.2 .2v.1l-.8 .8h.8M147.7 116.6h-.8l.6-.5v1.1M147.7 118.2l-.8 .5M153.4 114v1l.4 .4 .5-.4v-1M153.4 117.5v-1.3l.4 .4 .5-.4v1.3M154.3 118.5l-.2-.2h-.5l-.2 .2v.9l.2 .2h.5l.2-.2v-.5h-.5M154.7 116.4l.3-.2h.4l.3 .2v.9l-.3 .2h-.4l-.3-.2zM155.7 114.3l-.3-.3h-.4l-.3 .3v.9l.3 .2h.4l.3-.2M155.7 118.3v1.3l-1-1.3v1.3M156.1 118.3h.7l.2 .2v.9l-.2 .2h-.7zM157 114.3l-.2-.3h-.5l-.2 .3v.9l.2 .2h.5l.2-.2M157 116.4l-.2-.2h-.5l-.2 .2v.2l.2 .2h.5l.2 .3v.2l-.2 .2h-.5l-.2-.2"/>
<path d="M157.5 116.2h.4M157.5 117.5h.4M157.7 116.2v1.3M163.8 105.5l-.3-.2h-.4l-.2 .2v.9M163.8 105.5v.9l-.3 .3h-.4l-.2-.3M163.8 105.5l-.9 .9M164.2 106.4h.2v.3h-.2zM164.9 106.7h.9M164.9 105.8l.5-.5v1.4M166.3 105.8v.6l.2 .3h.7v-.9M167.2 109.7l-.3-.2h-.4l-.2 .2v.9l.2 .3h.4l.3-.3M167.6 106h.5"/>
<path d="M168.5 105.3h-.9v1.4M168.5 109.5h-.9v.7l.5-.2 .4 .2v.4l-.2 .3h-.5l-.2-.3M168.6 100.5l-.2-.2h-.4l-.3 .2v.9l.3 .2h.4l.2-.2v-.5h-.4M170 100.3v1.3l-.9-1.3v1.3M170.2 114v1l.5 .4 .4-.4v-1M170.5 100.3h.6l.2 .2v.9l-.2 .2h-.6zM172.5 114.3l-.2-.3h-.5l-.2 .3v.9l.2 .2h.5l.2-.2M173.8 114.3l-.2-.3h-.4l-.2 .3v.9l.2 .2h.4l.2-.2M174.4 105.7l.2-.2h.4l.2 .2v.2l-.8 .8h.8M175.5 105.9l.4-.4v1.2M175.5 103.6l.2-.2h.4l.2 .2-.2 .4M175.5 110.3h.6l.2 .4-.2 .2h-.4l-.2-.2z"/>
<path d="M175.5 106.7h.8M175.9 104h.2M176.1 104l.2 .2-.2 .4h-.4l-.2-.2M176.3 109.7l-.8 .6M176.3 108.2h-.8l.6-.6v1.2M180.6 108.6v.7l.4 .4 .3-.4v-.7M180.6 110.7v.7l.4 .4 .3-.4v-.7M181.3 104.5l-.2-.1h-.3l-.2 .1v.8l.2 .2h.3l.2-.2v-.4h-.3M181.3 106.7l-.2-.2h-.3l-.2 .2v.7l.2 .2h.3l.2-.2v-.4h-.3M182.5 110.9l-.2-.2h-.4l-.2 .2v.7l.2 .2h.4l.2-.2M182.5 104.4v1.1l-.8-1.1v1.1M182.5 106.5v1.1l-.8-1.1v1.1"/>
<path d="M182.5 108.8l-.2-.2h-.4l-.2 .2v.7l.2 .2h.4l.2-.2M182.9 104.4h.6l.2 .1v.8l-.2 .2h-.6zM182.9 106.5h.6l.2 .2v.7l-.2 .2h-.6zM183.7 110.9l-.2-.2h-.4l-.2 .2v.7l.2 .2h.4l.2-.2M183.7 108.8l-.2-.2h-.4l-.2 .2v.7l.2 .2h.4l.2-.2M196.3 107.2h.5l.2-.2v-.3l-.2-.2h-.5v1.1M197.4 106.5h.6l.2 .2v.7l-.2 .2h-.6zM198.6 119.9h.6l.1-.2v-.4l-.1-.2h-.6v1.1M199 111.4h.5l.2-.1v-.4l-.2-.2h-.5v1.1M199 105.1h.5l.2-.2v-.4l-.2-.1h-.5v1.1M199 103h.5l.2-.2v-.4l-.2-.1h-.5v1.1M199 113.5h.5l.2-.2v-.3l-.2-.2h-.5v1.1"/>
<path d="M199.3 107h-.7l.6-.5v1.1M199.7 100.9h.6l.2-.2v-.3l-.2-.2h-.6v1.1M199.7 119.1h.6l.2 .2-.2 .4 .2 .4-.2 .1h-.6zM199.7 119.7h.6M200.1 110.7h.6l.2 .2v.7l-.2 .2h-.6zM200.1 106.5l-.4 .3v.4l.4 .4M200.1 102.3h.6l.2 .1v.8l-.2 .2h-.6zM200.1 104.4h.6l.2 .1v.8l-.2 .2h-.6zM200.1 112.8h.6l.2 .2v.7l-.2 .2h-.6zM200.1 117.8h.6l.2-.2v-.4l-.2-.2h-.6v1.2M200.5 106.5l.8 1.1M200.9 109.3h.6l.2-.1v-.4l-.2-.2h-.6v1.1"/>
<path d="M200.9 100.2h.6l.2 .2v.7l-.2 .2h-.6zM200.9 119.5l.4-.4v1.1M201.3 102.4l.2-.1h.4l.2 .1v.2l-.8 .8h.8M201.3 104.5l.2-.1h.4l.2 .1-.2 .4M201.3 111.3h.6l.2 .3-.2 .2h-.4l-.2-.2zM201.3 112.8h.8l-.8 1.1M201.3 117h.6l.2 .2-.2 .4 .2 .3-.2 .3h-.6zM201.3 117.6h.6M201.3 106.5l-.8 1.1M201.7 104.9h.2M201.9 104.9l.2 .2-.2 .4h-.4l-.2-.2M202.1 108.6h.5l.2 .2v.7l-.2 .2h-.5z"/>
<path d="M202.1 100.5l.4-.3v1.1M202.1 110.7l-.8 .6M202.1 101.3h.7M202.5 106.7l-.3-.2h-.3l-.2 .2v.7l.2 .2h.3l.3-.2M202.5 119.1l-.4 .4v.4l.4 .3M202.8 106.5v1.1M202.8 102.3l-.3 .3v.4l.3 .4M202.8 104.4l-.3 .4v.3l.3 .4M202.8 110.7l-.3 .4v.3l.3 .4M202.8 112.8l-.3 .4v.3l.3 .4M203 119.1h.4l.2 .2v.8l-.2 .1h-.4l-.2-.1v-.8zM203 107l.6 .6"/>
<path d="M203.2 111.8v-.7l.4-.4 .4 .4v.7M203.2 113.9v-.7l.4-.4 .4 .4v.7M203.2 117.2v.7l-.2 .3h-.4l-.1-.3M203.2 104.4h.4M203.2 105.5h.4M203.2 117.2l-.2-.2h-.4l-.1 .2v.7M203.2 117.2l-.7 .7M203.2 113.3h.8M203.2 111.3h.8M203.2 102.3h.4M203.2 103.4h.4M203.4 102.3v1.1"/>
<path d="M203.4 104.4v1.1M203.6 106.5l-.8 .7M203.6 100.2l-.4 .3v.4l.4 .4M204 108.6h-.8v.6l.4-.3 .4 .3v.3l-.2 .2h-.4l-.2-.2M204 117l-.4 .4v.4l.4 .4M204 100.2h.8M204.4 110.7h.4M204.4 111.8h.4M204.4 118.2h.4M204.4 117h.4M204.4 112.8h.4M204.4 113.9h.4"/>
<path d="M204.4 100.2v1.1M204.6 110.7v1.1M204.6 112.8v1.1M204.6 117v1.2M204.8 102.3v1.1l-.8-1.1v1.1M204.8 104.4v1.1l-.8-1.1v1.1M204.8 119.3l-.2-.2h-.4l-.2 .2v.8l.2 .1h.4l.2-.1M204.8 108.6l-.4 .3v.4l.4 .4M204.8 106.5l-.8 1.1M205.2 104.4h.7M205.2 106.5h.7M205.2 108.6h.7"/>
<path d="M205.2 119.5l.3-.4v1.1M205.2 102.3h.7M205.2 100.2l.7 1.1M205.5 102.3v1.1M205.5 104.4v1.1M205.5 106.5v1.1M205.5 108.6v1.1M205.9 110.7v1.1l-.7-1.1v1.1M205.9 112.8v1.1l-.7-1.1v1.1M205.9 117.2l-.2-.2h-.3l-.2 .2v.7l.2 .3h.3l.2-.3M205.9 100.2l-.7 1.1M206.3 100.2h.6l.2 .2v.7l-.2 .2h-.6z"/>
<path d="M206.3 117.8h.6l.2-.2v-.4l-.2-.2h-.6v1.2M206.3 105.5h.8M206.3 109.7h.8M206.3 119.7h.8M206.3 113.2l.4-.4v1.1M206.3 113.9h.8M206.3 104.8l.4-.4v1.1M206.3 108.9l.4-.3v1.1M207.1 110.9l-.2-.2h-.4l-.2 .2v.7M207.1 102.4l-.2-.1h-.4l-.2 .1v.8M207.1 106.7l-.2-.2h-.4l-.2 .2v.7M207.1 106.7v.7l-.2 .2h-.4l-.2-.2"/>
<path d="M207.1 110.9v.7l-.2 .2h-.4l-.2-.2M207.1 102.4v.8l-.2 .2h-.4l-.2-.2M207.1 110.9l-.8 .7M207.1 106.7l-.8 .7M207.1 102.4l-.8 .8M207.5 100.2l.4 .3v.4l-.4 .4M207.5 102.3l.4 .3v.4l-.4 .4M207.5 104.4l.4 .4v.3l-.4 .4M207.5 106.5l.4 .3v.4l-.4 .4M207.5 108.6l.4 .3v.4l-.4 .4M207.5 110.7l.4 .4v.3l-.4 .4M207.5 112.8l.4 .4v.3l-.4 .4"/>
<path d="M207.5 117l.4 .4v.4l-.4 .4M207.5 119.1l.4 .4v.4l-.4 .3M212.1 113h.8M212.1 116.4l.4-.3v1.1M212.1 103.8l.4-.4v1.2M212.1 110.1l.4-.4v1.2M212.1 112.2l.4-.4v1.2M212.1 118.6l.4-.4v1.1M212.1 105.7l.2-.2h.4l.2 .2v.2l-.8 .8h.8M212.1 104.6h.8M212.1 110.9h.8M212.1 119.3h.8"/>
<path d="M212.1 117.2h.8M212.1 101.5l.2-.2h.4l.2 .2-.2 .4M212.5 101.9h.2M212.7 101.9l.2 .2-.2 .4h-.4l-.2-.2M212.9 108.2h-.6l-.2-.2 .2-.4h.4l.2 .2v.8l-.2 .2h-.4l-.2-.2M213.3 113h.8M213.3 116.2l.2-.1h.4l.2 .1v.2l-.8 .8h.8M213.3 101.5l.2-.2h.4l.2 .2v.2l-.8 .8h.8M213.3 118.4l.2-.2h.4l.2 .2-.2 .3M213.3 112.2l.4-.4v1.2M213.3 100.4h.8M213.7 118.7h.2"/>
<path d="M213.9 118.7l.2 .2-.2 .4h-.4l-.2-.2M214.1 109.9v.8l-.2 .2h-.4l-.2-.2M214.1 109.9l-.2-.2h-.4l-.2 .2v.8M214.1 109.9l-.8 .8M216.5 101.2h9M216.5 105.6h.9M216.5 108.6h.7l.2-.2v-.4l-.2-.3h-.7v1.4M216.5 102.8h.5M216.5 101.4h.5M216.7 101.4v1.4M217 108.6l.4 .5M217 105.6v1.4"/>
<path d="M217.9 105.6h.4M217.9 108.4h.4M217.9 107h.4M218.1 105.6v1.4M218.3 101.4v1.4l-.9-1.4v1.4M218.8 107.7h-.9v1.4h.9M218.8 107v-1.4l.4 .5 .5-.5v1.4M218.8 101.4h.9M219.2 101.4v1.4M219.2 100.2h.7l.2-.2v-.5l-.2-.2h-.7v1.4M219.2 109.3h.9M219.7 100.2l.4 .5"/>
<path d="M220.1 103h.9M220.1 106.3h.5M220.6 100.9h.9M221 105.6h-.9v1.4h.9M221.5 107.2h.9M221.5 108l-.2-.3h-.5l-.2 .3 .2 .4h.5l.2 .2-.2 .5h-.5l-.2-.2M222 107.7v1.4l.4-.5 .4 .5v-1.4M222.4 101.6l-.2-.2h-.5l-.2 .2 .2 .5h.5l.2 .2v.3l-.2 .2h-.5l-.2-.2M222.8 101.6l.3-.2h.4l.3 .2v1l-.3 .2h-.4l-.3-.2zM222.8 107v-1.4l.5 .5 .5-.5v1.4M223.3 102.3l.5 .5M224.2 101.4v1.4l.5-.5 .4 .5v-1.4"/>
<path d="M224.4 105.6h.5l.2 .3v.9l-.2 .2h-.5l-.2-.2v-.9zM224.9 110.7h-.9v.7l.5-.3h.2l.2 .3v.4l-.2 .2h-.4l-.3-.2M225.4 111.4h.7l.2 .4-.2 .2h-.5l-.2-.2zM225.4 115.5h.7l.2-.2v-.4l-.2-.2h-.7v1.3M225.6 105.6h.6l.3 .3v.9l-.3 .2h-.6zM225.8 115.5l.5 .5M226.3 110.7l-.9 .7M226.7 114.7h.9v.2l-.9 .9v.2M226.9 106.3h.5M227.6 110.9l-.2-.2h-.4l-.3 .2v.9M227.6 110.9v.9l-.2 .2h-.4l-.3-.2M227.6 110.9l-.9 .9"/>
<path d="M227.8 105.6h-.9v1.4h.9M228.3 107.2h.9M229 108.7v.2l.4 .4M229.4 109.3v.7M229.6 110.5h.9M229.9 108.7v.2l-.5 .4M230 110.5v1.3M230.4 109.3h.4M230.5 105.9l-.2-.3h-.5l-.2 .5 .2 .2h.5l.2 .5-.2 .2h-.5l-.2-.2M230.9 111.8h.5M230.9 110.5h.5M231 106.3h.4"/>
<path d="M231.2 110.5v1.3M231.3 108.7h-.9v1.3h.9M231.7 108.7v1.3h.9M231.9 111.8v-1.3l.4 .4 .4-.4v1.3M231.9 105.6h-.9v1.4h.9M232.3 105.6h.9M232.8 105.6v1.4M233.1 108.7v1.3h.9M233.2 111.1h.5M234.1 110.5h-.9v1.3h.9M234.6 112h.9M234.7 108.7h.4l.2 .2v.9l-.2 .2h-.4l-.3-.2v-.9z"/>
<path d="M235.8 108.7v1.3l.4-.4 .5 .4v-1.3M235.9 111.8v-1.3l.5 .4 .4-.4v1.3M236.9 102.6v.4M236.9 103.5v.9M236.9 103.9h1.4M236.9 102.8h1.4M237.3 110.7l.2-.2h.5l.2 .2v.9l-.2 .2h-.5l-.2-.2zM237.6 100.3v.5M238.1 116.9l-.3-.2h-.4l-.2 .2v.9l.2 .2h.4l.3-.2v-.5h-.5M238.1 106.4l-.3-.2h-.4l-.2 .2v.9l.2 .2h.4l.3-.2v-.5h-.5M238.3 102.6v.4M238.3 101.2h-1.4l.5 .5-.5 .4h1.4"/>
<path d="M238.6 110.5h.7l.2 .2v.9l-.2 .2h-.7zM239.4 106.2v1.3l-.9-1.3v1.3M239.4 116.7v1.3l-.9-1.3v1.3M239.9 116.7h.7l.2 .2v.9l-.2 .2h-.7zM239.9 106.2h.7l.2 .2v.9l-.2 .2h-.7zM240 111.1h.5M240.3 101l-.2 .2v.5l.2 .2 .5-.2v-.5l.2-.2 .4 .2v.5l-.2 .2M240.9 110.5h-.9v1.3h.9M241 100.5v-.6l-.2-.3h-.5l-.2 .3v.6h1.3M68.5 121.1l-.2-.2h-.4l-.3 .2v.9l.3 .2h.4l.2-.2v-.4h-.4M69.9 120.9v1.3l-.9-1.3v1.3M70.4 120.9h.6l.3 .2v.9l-.3 .2h-.6z"/>
<path d="M138.7 123.6v-.9l.4-.4 .5 .4v.9M138.7 122.9h.9M140 122.3v.8l.5 .5 .4-.5v-.8M141.4 123.1h.6l.3-.2v-.4l-.3-.2h-.6v1.3M141.8 123.1l.5 .5M142.7 123.8h.9M145 122.5l-.2-.2h-.5l-.2 .2 .2 .4h.5l.2 .2v.3l-.2 .2h-.5l-.2-.2M145.5 123.1h.6l.2-.2v-.4l-.2-.2h-.6v1.3M146.8 122.3h.5M146.8 123.6h.5M147 122.3v1.3M147.7 123.8h.9"/>
<path d="M149.1 123.1h.6l.3-.2v-.4l-.3-.2h-.6v1.3M150.4 123.1h.7l.2-.2v-.4l-.2-.2h-.7v1.3M150.9 123.1l.4 .5M152 122.3h.4l.3 .2v.9l-.3 .2h-.4l-.2-.2v-.9zM154 122.5l-.2-.2h-.4l-.3 .2v.9l.3 .2h.4l.2-.2v-.5h-.4M156 125.3l-.2-.2h-.5l-.2 .2v.9l.2 .2h.5l.2-.2v-.4h-.4M157.4 125.1v1.3l-.9-1.3v1.3M157.8 125.1h.7l.2 .2v.9l-.2 .2h-.7zM178.6 130.9v1.1l.3 .2h.4l.2-.2v-1.1M180.9 131.6h-.9l.7-.7v1.3M194.3 124.1h.6l.2-.2v-.4l-.2-.2h-.6v1.2M195.1 122h.6l.2-.2v-.4l-.2-.2h-.6v1.1"/>
<path d="M195.5 123.3h.5l.3 .2-.3 .4 .3 .4-.3 .2h-.5zM195.5 123.9h.5M196.3 121.2h.5l.2 .2-.2 .4 .2 .4-.2 .1h-.5zM196.3 121.8h.5M196.6 123.5l.2-.2h.4l.2 .2-.2 .4M197 123.9h.2M197.2 123.9l.2 .2-.2 .4h-.4l-.2-.2M197.4 121.4l.2-.2h.4l.2 .2v.2l-.8 .7h.8M198.2 123.3l-.4 .4v.4l.4 .4M198.6 124.5v-1.2l.4 .4 .3-.4v1.2M199 126.2h.5l.2-.2v-.4l-.2-.2h-.5v1.2M199 121.2l-.4 .4v.4l.4 .3"/>
<path d="M199.7 128.3h.6l.2-.2v-.4l-.2-.2h-.6v1.2M199.9 123.3h.4l.2 .2v.8l-.2 .2h-.4l-.2-.2v-.8zM200.1 125.4h.6l.2 .2-.2 .4 .2 .4-.2 .2h-.6zM200.1 121.4l-.2-.2h-.4l-.2 .2 .2 .4h.4l.2 .2-.2 .3h-.4l-.2-.1M200.1 126h.6M200.9 127.5h.6l.2 .2-.2 .4 .2 .4-.2 .2h-.6zM200.9 128.1h.6M200.9 120.2h.8M201.3 121.4l-.2-.2h-.4l-.2 .4 .2 .2h.4l.2 .4-.2 .1h-.4l-.2-.1M201.7 123.5l-.2-.2h-.4l-.2 .2 .2 .4h.4l.2 .2-.2 .4h-.4l-.2-.2M202.1 126h-.8l.6-.6v1.2M202.1 123.3h.4"/>
<path d="M202.1 124.5h.4M202.2 123.3v1.2M202.5 121.2l-.8 1.1M202.8 127.5h-.7v.6l.4-.2 .3 .2v.4l-.2 .2h-.4l-.1-.2M202.8 125.4l-.3 .4v.4l.3 .4M203 121.2h.4l.2 .2v.8l-.2 .1h-.4l-.2-.1v-.8zM203.2 126.6v-1.2l.4 .4 .4-.4v1.2M203.6 123.3l-.8 1.2M203.6 127.5l-.4 .4v.4l.4 .4M204.2 123.3h.4l.2 .2v.8l-.2 .2h-.4l-.2-.2v-.8zM204.4 126.6h.4M204.4 125.4h.4"/>
<path d="M204.6 125.4v1.2M204.8 127.7l-.2-.2h-.4l-.2 .2 .2 .4h.4l.2 .2-.2 .4h-.4l-.2-.2M204.8 121.4l-.2-.2h-.4l-.2 .2v.8l.2 .1h.4l.2-.1M205.2 122.3h.7M205.2 121.6l.3-.4v1.1M205.2 120.2h.7M205.9 123.5l-.2-.2h-.3l-.2 .2v.8l.2 .2h.3l.2-.2M205.9 127.7l-.2-.2h-.3l-.2 .2v.8l.2 .2h.3l.2-.2M205.9 125.6l-.2-.2h-.3l-.2 .4 .2 .2h.3l.2 .4-.2 .2h-.3l-.2-.2M206.3 123.5l.2-.2h.4l.2 .2v.2l-.8 .8h.8M206.3 120.2v-.7l.4-.4 .4 .4v.7M206.3 121.2h.6l.2 .2-.2 .4 .2 .4-.2 .1h-.6z"/>
<path d="M206.3 127.5v1.2M206.3 121.8h.6M206.5 125.4h.4l.2 .2v.8l-.2 .2h-.4l-.2-.2v-.8zM206.5 128.1l.6 .6M207.1 127.5l-.8 .8M207.5 127.5l.4 .4v.4l-.4 .4M207.5 121.2l.4 .4v.4l-.4 .3M207.5 123.3l.4 .4v.4l-.4 .4M207.5 125.4l.4 .4v.4l-.4 .4M212.1 127l.4-.4v1.1M212.1 120.6l.4-.3v1.1M212.1 122.8l.4-.4v1.1"/>
<path d="M212.1 124.9l.4-.4v1.1M212.1 127.7h.8M212.1 125.6h.8M212.1 123.5h.8M212.1 121.4h.8M213.3 126.6h.8v.2l-.8 .8v.1M213.3 125.1h.6l.2 .3-.2 .2h-.4l-.2-.2zM214.1 122.4h-.8v.6l.4-.2 .4 .2v.3l-.2 .2h-.4l-.2-.2M214.1 124.5l-.8 .6M214.1 120.8h-.8l.6-.5v1.1M216.5 123.8v-1.3l.5 .4 .4-.4v1.3M216.5 125.9v-1.3l.5 .4 .4-.4v1.3"/>
<path d="M217.4 126.9l-.2-.2h-.5l-.2 .2v.2l.2 .2h.5l.2 .5-.2 .2h-.5l-.2-.2M217.9 122.7l.2-.2h.4l.3 .2v.9l-.3 .2h-.4l-.2-.2zM217.9 125.9h.4M217.9 124.6h.4M218.1 124.6v1.3M218.8 126.9l-.3-.2h-.4l-.2 .2v.9l.2 .2h.4l.3-.2M219.2 126.7v1.3M219.5 127.3l.6 .7M219.7 124.8l-.2-.2h-.5l-.2 .4 .2 .2h.5l.2 .5-.2 .2h-.5l-.2-.2M220.1 122.7l-.2-.2h-.4l-.3 .2 .3 .4h.4l.2 .3v.2l-.2 .2h-.4l-.3-.2M220.1 126.7l-.9 .9M220.4 124.6h.4l.2 .2v.9l-.2 .2h-.4l-.3-.2v-.9z"/>
<path d="M220.6 123.8h.4M220.6 122.5h.4M220.8 122.5v1.3M54 159.8h1.3l-1.3 .9h1.3M54.2 158.5h.9l.2 .2v.7h-1.3v-.7zM58.7 154.5h.9l.4 .4-.4 .5h-.9M58.9 153.1l-.2 .3v.4l.2 .2h.9l.2-.2v-.4l-.2-.3M58.9 151.8l-.2 .2v.4l.2 .3h.9l.2-.3v-.4l-.2-.2M60.8 156.1v.9l.5 .5 .4-.5v-.9M61.7 158.5l-.2-.3h-.5l-.2 .3v.9l.2 .2h.5l.2-.2v-.5h-.4M63.1 156.4l-.3-.3h-.4l-.2 .3v.8l.2 .3h.4l.3-.3M63.1 158.2v1.4l-.9-1.4v1.4"/>
<path d="M63.5 158.2h.7l.2 .3v.9l-.2 .2h-.7zM64.4 156.4l-.2-.3h-.4l-.3 .3v.8l.3 .3h.4l.2-.3M70.3 156.6h.6l.2 .4-.2 .2h-.4l-.2-.2zM71.1 158.1h-.8v.6l.4-.2 .4 .2v.4l-.2 .2h-.4l-.2-.2M71.1 156l-.8 .6M54.2 161.2l-.2 .2v.4l.2 .3h.9l.2-.3v-.4l-.2-.2h-.4v.4M59.6 160.6l-.2-.3h-.5l-.2 .5 .2 .2h.5l.2 .2v.3l-.2 .2h-.5l-.2-.2M59.6 162.7l-.2-.3h-.5l-.2 .3v.2l.2 .2h.5l.2 .2v.3l-.2 .2h-.5l-.2-.2M59.6 164.8l-.2-.3h-.5l-.2 .3 .2 .4h.5l.2 .2-.2 .5h-.5l-.2-.2M59.6 166.9l-.2-.3h-.5l-.2 .5 .2 .2h.5l.2 .5-.2 .2h-.5l-.2-.2M60.1 160.3h.6l.3 .3v.9l-.3 .2h-.6zM60.1 165.2h.4"/>
<path d="M60.1 167.3h.4M61 162.7l-.3-.3h-.4l-.2 .3v.9l.2 .2h.4l.3-.2M61 164.5h-.9v1.4h.9M61 166.6h-.9v1.4h.9M61.4 161.7v-.9l.5-.5 .4 .5v.9M61.4 161h.9M61.4 162.4v1.4h.9M61.4 165.4h.7l.2-.2v-.4l-.2-.3h-.7v1.4M61.4 167.6h.7l.2-.3v-.4l-.2-.3h-.7v1.4M61.9 165.4l.4 .5M61.9 167.6l.4 .4M62.8 166.1h.9"/>
<path d="M62.8 168.2h.9M64.1 165.4h.7l.2-.2v-.4l-.2-.3h-.7v1.4M64.1 166.6h.9M64.6 165.4l.4 .5M64.6 166.6v1.4M65.5 164.5l.9 1.4M65.5 166.6l.9 1.4M66.4 164.5l-.9 1.4M66.4 166.6l-.9 1.4M68.6 170.8h.5M68.9 170.8v1.1l-.3 .2h-.2l-.2-.2M69.5 171.7h.7l.2-.3v-.4l-.2-.2h-.7v1.3"/>
<path d="M70.3 166.9l.4-.3v1.1M70.3 167.7h.8M70.3 164.7l.2-.3h.4l.2 .3v.1l-.8 .8h.8M70.3 162.5l.2-.2h.4l.2 .2-.2 .4M70.7 162.9h.2M70.9 172.1h.9M70.9 171.2l.4-.4v1.3M70.9 162.9l.2 .2-.2 .4h-.4l-.2-.2M71.1 160.8h-.8l.6-.5v1.1"/>
</g>
<path d="M10.2 10.2h242v189.4h-242zM123.9 14.5v180.9M14.5 58.7h233.5M14.5 142.8h233.5" fill="none" stroke="#800000" stroke-width=".25"/>
<g fill="none" stroke="#800000" stroke-width=".21">
<path d="M13.4 13.4h235.7v183.1h-235.7zM27.2 11.5l.7-.7v2M27.2 12.8h1.4M42.9 10.2v3.2M56.7 11.2l.3-.4h.7l.3 .4v.3l-1.3 1.3h1.3M72.3 10.2v3.2M86.1 11.2l.4-.4h.6l.4 .4v.3l-.4 .3M86.8 11.8h.3M87.1 11.8l.4 .4v.3l-.4 .3h-.6l-.4-.3M101.8 10.2v3.2M116.9 11.8h-1.3l1-1v2M131.2 10.2v3.2"/>
<path d="M146.4 10.8h-1.3v1l.6-.3h.3l.4 .3v.7l-.4 .3h-.6l-.3-.3M160.7 10.2v3.2M163.9 16.6l1 1.5M163.9 16.6l-1.1 1.5M163.9 16.6v2.1M174.5 11.8h1l.4 .4v.3l-.4 .3h-.6l-.4-.3zM175.9 10.8l-.7 .4-.7 .6M190.2 10.2v3.2M204 10.8h1.3v.4l-1.3 1.3v.3M219.6 10.2v3.2M220.7 16.6v2.1M220.7 16.6l1 1.5"/>
<path d="M220.7 16.6l-1.1 1.5M227 16.6v2.1M227 16.6l1 1.5M227 16.6l-1.1 1.5M233.8 11.8l-.4-.3v-.3l.4-.4h.6l.4 .4v.3l-.4 .3M233.8 11.8l-.4 .4v.3l.4 .3h.6l.4-.3v-.3l-.4-.4M233.8 11.8h.6M10.9 32.7v-1.3l.7-.7 .6 .7v1.3M10.9 31.7h1.3M40.2 33.4l.5-1.1 .6 1.1h8.9M45 28.1h-3.7a1.06 1.06 0 0 0-1.1 1.1 1.06 1.06 0 0 0 1.1 1h3.7M45 27.6h1v3.2h-1z"/>
<path d="M45.6 32.3h.8l-.4 1.1zM45.6 32.4h.8M45.7 32.6h.7M45.7 32.6h.6M45.8 32.7h.5M45.8 32.8h.4M45.8 32.9h.4M45.9 33h.3M45.9 33.1h.2M45.9 33.2h.2M46 33.3h.1M46 29.2h4.2"/>
<path d="M50.2 31.3h-4.2v2.1M58.7 33.4h4.1M60.7 31.3v2.1M60.7 34.2v3.4M69.2 33.4h4.2M71.3 31.3v2.1M71.3 34.2v3.4M77.6 29.2h2.1M83.9 33.4v2.1M83.9 39.7v2.1M88.1 29.2h2.1M94.4 25l-1 1.6"/>
<path d="M94.4 25l1.1 1.6M94.4 25v2.1M159.6 22.9v2.1l.9 .3-1.7 .5 1.7 .6-1.7 .5 1.7 .5-1.7 .5 1.7 .5-1.7 .6 .8 .2v2.1M166 22.9h4.2M167 29.2h2.1l-1 1zM168.1 20.8v2.1M168.1 23.7v5.5M174.4 33.4h4.2M174.4 31.3h4.2M174.4 35.5h4.2M174.4 37.6h4.2M174.4 39.7h4.2"/>
<path d="M178.6 27.1h23.1v23.1h-23.1zM201.7 33.4h4.2M201.7 31.3h4.2M201.7 35.5h4.2M201.7 37.6h4.2M201.7 39.7h4.2M220.7 20.8v2.1l.8 .3-1.7 .5 1.7 .6-1.7 .5 1.7 .5-1.7 .5 1.7 .6-1.7 .5 .9 .2v2.1M220.7 37.6v4.7M227 22.9v2.1l.8 .3-1.7 .5 1.7 .6-1.7 .5 1.7 .5-1.7 .5 1.7 .5-1.7 .6 .9 .2v2.1M249.7 31.7h1.4M249.7 32.7v-1.3l.7-.7 .7 .7v1.3M10.2 50h3.2"/>
<path d="M82.8 41.8h2.1l-1 1.1zM169.1 50.2h2.1l-1 1.1zM170.2 48.1v2.1M174.4 41.8h4.2M174.4 43.9h4.2M174.4 46h4.2M201.7 41.8h4.2M201.7 43.9h4.2M201.7 46h4.2M211.2 50.2h2.1l-1 1.1zM212.3 48.1v2.1M219.6 50.2h2.1l-1 1.1z"/>
<path d="M220.7 43.4v2.6M220.7 48.1v2.1M249.1 50h3.1M10.9 67.3h1l.3 .4v.3l-.3 .3 .3 .4v.3l-.3 .3h-1zM10.9 68.3h1M170.2 65v2.1M170.2 69.2v2.1l.8 .2-1.7 .5 1.7 .5-1.7 .6 1.7 .5-1.7 .5 1.7 .5-1.7 .6 .9 .3v2.1M170.2 65l1 1.5M170.2 65l-1.1 1.5M174.4 79.7h2.6M178.6 77.6h31.5v52.6h-31.5zM210.1 79.7h4.3"/>
<path d="M239.6 77.6v2.1M239.6 77.6l1.1 1.6M239.6 77.6l-1.1 1.6M249.7 67.3h1l.4 .4v.3l-.4 .3 .4 .4v.3l-.4 .3h-1zM249.7 68.3h1M10.2 86.6h3.2M35.5 94.4v2.1l.8 .3-1.7 .6 1.7 .5-1.7 .5 1.7 .5-1.7 .6 1.7 .5-1.7 .5 .9 .2v2.1M35.5 88.1v2.1M35.5 88.1l-1.1 1.6M35.5 88.1l1.1 1.6M43.9 89.2v3.1M46 89.2v3.1"/>
<path d="M68.1 91.3h2.1M69.2 81.8v2.1M69.2 90.2v4.2M69.2 91.3l1 2.1h-2.1zM69.2 81.8l-1.1 1.6M69.2 81.8l1 1.6M73.4 88.1h2.1a1.06 1.06 0 0 1 1 1.1 1.06 1.06 0 0 1-1 1 1.05 1.05 0 0 1 1 1.1 1.05 1.05 0 0 1-1 1 1.06 1.06 0 0 1 1 1.1 1.06 1.06 0 0 1-1 1 1.05 1.05 0 0 1 1 1.1 1.05 1.05 0 0 1-1 1h-2.1M77 88.1v8.4M78.1 88.1v8.4M79.7 89.7l.5-.8-.5-.8v8.4M82.6 89.7l-.8 4.2v2.6M82.6 88.1l.5 .8-.5 .8"/>
<path d="M82.6 88.1v1.6M82.6 88.1l-.6 .8 .6 .8M83.9 89.7l-.5-.8 .5-.8v8.4M160.7 81.8l1.1-1 1 1zM161.8 81.8v4.6M161.8 87.7v2.5M166 90.2l1 1.6M166 90.2l-1.1 1.6M166 90.2v2.1M174.4 88.1h4.2M174.4 98.6h4.2M174.4 94.4h4.2"/>
<path d="M174.4 83.9h4.2M174.4 86h4.2M210.1 88.1h4.3M210.1 98.6h4.3M210.1 94.4h4.3M210.1 83.9h4.3M210.1 86h4.3M210.1 92.3h4.3M210.1 90.2h4.3M210.1 81.8h4.3M238.5 95l1.1 3.6v2.1M239.6 81.8v2.1l.9 .3-1.7 .5 1.7 .6-1.7 .5 1.7 .5-1.7 .5 1.7 .6-1.7 .5 .8 .2v2.1"/>
<path d="M239.6 92.3v2.7M249.1 86.6h3.1M12.2 104.3l-.3-.4h-.7l-.3 .4v1.3l.3 .3h.7l.3-.3M37.6 107h4.7v4.3h-4.7M41.3 108.1h2.1l-1.1 2.1zM41.3 110.2h2.1M44.3 108.3l.8-.3-.4 .7zM44.4 109.3l.8-.4-.3 .8zM45.1 108l-1.2 1.2M45.2 108.9l-1.2 1.2M47.5 110l.4 1-1-.4zM52.3 107h-4.2l-2.1 2.2 2.1 2.1h4.2"/>
<path d="M54.4 111.3h2.1l.4-.9 .5 1.7 .5-1.7 .5 1.7 .5-1.7 .6 1.7 .5-1.7 .5 1.7 .2-.8h2.1M65 111.3h2.1M67.3 112.4l1 .5M68.1 119.7h2.1l-1 1zM68.5 112.5l.7 .8h-1.1zM68.5 112.9l.1 .2h-.3l.2-.4 .5 .5h-.7M69.2 107v2.2l-1.7 .8M69.2 113.3v2.2M69.2 117.6v2.1M88.1 100.7h2.1M88.1 104.9h2.1M136.2 115.2v-.6l.3 .2 .2-.2v.6"/>
<path d="M136.5 119.7h4.7M136.5 117.6h4.7M136.5 115.5h4.7M136.8 119.2l.4-.1-.1-.3h-.3v.6M136.9 115.2h.2M136.9 114.6h.2M137 119.2l.2 .2M137 114.6v.6M137.1 116.8h-.4l.4 .3-.1 .2-.3-.1M137.7 116.8h-.4l.1 .5 .3-.1M137.7 114.7h-.4l.4 .3-.1 .2-.3-.1M137.8 118.9h-.4l.4 .3-.1 .2-.3-.1"/>
<path d="M137.9 116.7v.6M138 118.8h.4M138 114.6l.3 .1-.1 .5-.3-.1zM138 117l.3 .3M138.2 118.8v.6M138.3 116.7l-.4 .4M146.6 119.7h4.6M146.6 117.6h4.6M146.6 115.5h4.6M149.5 114.6v.4l.2 .2 .2-.2v-.4M149.5 117.3v-.6l.2 .2 .2-.2v.6M149.9 118.9h-.4l.1 .5 .3-.1v-.2h-.2"/>
<path d="M150.2 116.7l.3 .1-.1 .5-.3-.1zM150.5 114.7h-.4v.4h.4M150.5 118.8v.6l-.4-.6v.6M150.7 118.8l.4 .1-.1 .5h-.3zM151.1 116.8h-.4l.4 .3-.1 .2-.3-.1M151.1 114.7h-.4v.4h.4M151.3 116.7h.2M151.3 117.3h.2M151.4 116.7v.6M169.1 102.8l1.1-1 1 1zM169.1 111.8l1.1 1.5M170.2 102.8v4.7"/>
<path d="M170.2 108.7v4.6M171.2 111.8l-1 1.5M174.4 104.9h4.2M174.4 107h4.2M174.4 109.2h4.2M174.4 111.3h4.2M210.1 119.7h4.3M210.1 100.7h4.3M210.1 104.9h4.3M210.1 107h4.3M210.1 109.2h4.3M210.1 111.3h4.3"/>
<path d="M210.1 117.6h4.3M210.1 113.3h4.3M210.1 102.8h4.3M220.7 113.3h2.1l.2-.8 .5 1.7 .5-1.7 .6 1.7 .5-1.7 .5 1.7 .5-1.7 .6 1.7 .3-.9h2.1M231.2 113.3h6.3M233.3 112.3l2.1 1-2.1 1.1zM233.9 115l1.2 1.2M234.4 115.9h.5M234.4 115.8h.5M234.5 115.7h.4M234.6 116h.4M234.6 115.6h.2"/>
<path d="M234.7 115.5h.1M234.8 115.5l.3 .7-.7-.3zM234.8 116.1h.2M234.9 114.9l1.1 1.2M235.1 116.2h.1M235.4 115.8h.5M235.4 115.7h.5M235.4 112.3v2.1M235.5 115.6h.3M235.5 115.5h.3M235.6 115.9h.3M235.6 115.4h.2"/>
<path d="M235.7 115.4l.3 .7-.7-.3zM235.8 116h.2M236 116.1h.1M238.5 104.9h2.2l-1.1 1.1zM238.5 115.5h2.2l-1.1 1zM239.6 102.8v2.1M239.6 113.3v2.2M251.1 104.3l-.4-.4h-.6l-.4 .4v1.3l.4 .3h.6l.4-.3M10.2 123.3h3.2M156.5 123.9h2.1l-1.1 1zM157.5 121.8v2.1M210.1 128.1h4.3"/>
<path d="M210.1 126h4.3M210.1 123.9h4.3M210.1 121.8h4.3M249.1 123.3h3.1M10.2 159.9h3.2M10.9 140.5h1l.3 .4v1.3l-.3 .3h-1zM55.5 159.6l1-1v2.1zM56.5 159.6h2.2M58.7 157.5h2M58.7 157.5l1.5 1.1M60.2 156.5l-1.5 1M71.3 159.6h.4"/>
<path d="M71.3 157.5h.4M249.1 159.9h3.1M249.7 140.5h1l.4 .4v1.3l-.4 .3h-1zM10.9 178.2h.7M12.2 177.2h-1.3v2h1.3M71.3 168.1h.4M71.3 166h.4M71.3 163.9h.4M71.3 161.8h.4M163.9 166h84.1v29.4h-84.1zM163.9 176.5h84.1M165 177.6h1.3"/>
<path d="M165.6 177.6v2M166.9 177.6h.7M166.9 179.6h.7M167.3 177.6v2M168.2 177.6h1.3M168.9 177.6v2M170.2 177.6v2h1.2M172.1 178.6h.6M173.4 177.6h-1.3v2h1.3M174 179.2h.3v.4h-.3zM174 178.3h.3v.3h-.3zM178.7 179.6v-2l.6 .7 .7-.7v2"/>
<path d="M180.9 178.3h.7l.3 .3v1h-1l-.3-.4 .3-.3h1M182.5 179.6h.7M182.5 178.3h.4v1.3M182.9 177.3v.3M183.8 179.6v-1.3h1l.3 .3v1M185.8 179.9h1.3M187.7 177.6v2h1l.3-.4v-.6l-.3-.3h-1M189.7 178.6l.3-.3h.6l.3 .3v.6l-.3 .4h-.6l-.3-.4zM191.9 178.3h.7l.3 .3v1h-1l-.3-.4 .3-.3h1M193.5 178.3v1.3M194.5 178.3h-.3l-.7 .6M196.4 177.6v2h-.9l-.4-.4v-.6l.4-.3h.9"/>
<path d="M249.7 178.2h.7M251.1 177.2h-1.4v2h1.4M27.2 197.7l.7-.7v2.1M27.2 199.1h1.4M42.9 196.5v3.1M56.7 197.4l.3-.4h.7l.3 .4v.3l-1.3 1.4h1.3M72.3 196.5v3.1M86.1 197.4l.4-.4h.6l.4 .4v.3l-.4 .3M86.8 198h.3M87.1 198l.4 .4v.3l-.4 .4h-.6l-.4-.4M101.8 196.5v3.1M116.9 198h-1.3l1-1v2.1"/>
<path d="M131.2 196.5v3.1M146.4 197h-1.3v1l.6-.3h.3l.4 .3v.7l-.4 .4h-.6l-.3-.4M160.7 196.5v3.1M163.9 182.8h84.1M163.9 191.2h84.1M165 183.9h1l.3 .4v1.2l-.3 .4h-1zM165 192.3h1l.3 .4v1.3l-.3 .3h-1zM166.9 184.9l.4-.3h.6l.3 .3v.6l-.3 .4h-.6l-.4-.4zM167.3 193h.6l.3 .3v1h-.9l-.4-.3 .4-.4h.9M168.9 193h.6M169.2 192.7v1.3l.3 .3M170.2 193.6h1.2v-.3l-.3-.3h-.6l-.3 .3v.7l.3 .3h.6"/>
<path d="M170.2 184.6h-1l-.3 .3v.6l.3 .4h1M170.8 184.6v.9l.3 .4h1v-1.3M172.1 194h.3v.3h-.3zM172.1 193h.3v.3h-.3zM173.4 184.9l-.3-.3h-.4v1.3M173.4 184.9l.3-.3 .3 .3v1M173.4 184.9v1M174.5 192.7l.3-.4h.6l.3 .4v.3l-1.2 1.3h1.2M174.5 198h1l.4 .4v.3l-.4 .4h-.6l-.4-.4zM174.7 185.2h1.3v-.3l-.4-.3h-.6l-.3 .3v.6l.3 .4h.6M175.9 197l-.7 .4-.7 .6M176.4 194.3h1.3"/>
<path d="M176.4 193l.6-.7v2M176.6 185.9v-1.3h1l.3 .3v1M178.6 184.6h.6M178.9 184.3v1.2l.3 .4M179.6 192.3l-1.3 2M181.6 192.7v1.3l-.3 .3h-.7l-.3-.3M181.6 192.7l-.3-.4h-.7l-.3 .4v1.3M181.6 192.7l-1.3 1.3M182.2 192.7l.3-.4h.7l.3 .4v.3l-.3 .3M182.9 193.3h.3M183.1 183.9v2l-1.3-2v2M183.2 193.3l.3 .3v.4l-.3 .3h-.7l-.3-.3"/>
<path d="M183.7 184.6v.9l.3 .4h1v-1.3M185.4 192.3l-1.3 2M186.1 194.3h1.3M186.1 193l.6-.7v2M186.3 184.9l-.3-.3h-.3v1.3M186.3 184.9v1M186.3 184.9l.3-.3 .3 .3v1M187.6 183.9v2h1l.3-.4v-.6l-.3-.3h-1M189.3 193.3h-1l-.3-.3v-.3l.3-.4h.7l.3 .4v1.3l-.3 .3h-.7l-.3-.3M189.5 185.2h1.3v-.3l-.3-.3h-.6l-.4 .3v.6l.4 .4h.6M190.2 196.5v3.1M191.5 184.6v1.3"/>
<path d="M191.9 192.7l.3-.4h.7l.3 .4v.3l-1.3 1.3h1.3M192.4 184.6h-.3l-.6 .6M193.1 185.5h.3v.4h-.3zM193.1 184.6h.3v.3h-.3zM193.8 192.7l.4-.4h.6l.3 .4v.3l-.3 .3M194.5 193.3h.3M194.8 193.3l.3 .3v.4l-.3 .3h-.6l-.4-.3M195.8 194h.3v.3h-.3zM195.8 193h.3v.3h-.3zM196.7 194.3h1.3M196.7 193l.7-.7v2M199 193.3l-.3 .3v.4l.3 .3h.6l.4-.3v-.4l-.4-.3"/>
<path d="M199 193.3l-.3-.3v-.3l.3-.4h.6l.4 .4v.3l-.4 .3M199 193.3h.6M204 197h1.3v.4l-1.3 1.3v.4M219.6 196.5v3.1M222.8 191.2v4.2M225.2 192.7l-.3-.4h-.7l-.3 .4v.3l.3 .3h.7l.3 .3v.4l-.3 .3h-.7l-.3-.3M225.8 193.3l.4-.3h.6l.3 .3v1M225.8 192.3v2M227.8 193.6h1.3v-.3l-.4-.3h-.6l-.3 .3v.7l.3 .3h.6M229.7 193.6h1.3v-.3l-.3-.3h-.7l-.3 .3v.7l.3 .3h.7M231.7 193h.6M232 192.7v1.3l.3 .3"/>
<path d="M233 194h.3v.3h-.3zM233 193h.3v.3h-.3zM233.8 198l-.4 .4v.3l.4 .4h.6l.4-.4v-.3l-.4-.4M233.8 198l-.4-.3v-.3l.4-.4h.6l.4 .4v.3l-.4 .3M233.8 198h.6M235.5 194.3h1.3M235.5 193l.6-.7v2M236.5 182.8v8.4M237.6 185.2h.9l.4-.3v-.6l-.4-.4h-.9v2M238.2 185.2l.7 .7M238.7 192.3l-1.3 2M239.4 194.3h1.2"/>
<path d="M239.4 193l.6-.7v2M239.5 184.9h.7M239.7 187.6l.3-.2h.5l.3 .2v.3l-.3 .3M240.2 188.2h.3M240.5 188.2l.3 .3v.2l-.3 .3h-.5l-.3-.3M240.8 183.9h-1.3v2h1.3M241.3 188.7h.3v.3h-.3zM241.5 183.9v1.3l.6 .7 .7-.7v-1.3M243.3 187.6l-.3-.2h-.5l-.3 .2v1.1M243.3 187.6v1.1l-.3 .3h-.5l-.3-.3M243.3 187.6l-1.1 1.1M243.4 185.5h.3v.4h-.3z"/>
<path d="M243.4 184.6h.3v.3h-.3z"/>
<circle cx="177.8" cy="79.7" r=".83"/>
<circle cx="91.2" cy="100.7" r="1.06"/>
<circle cx="91.2" cy="104.9" r="1.06"/>
<circle cx="142" cy="115.5" r=".83"/>
<circle cx="142" cy="119.7" r=".83"/>
<circle cx="142" cy="117.6" r=".83"/>
<circle cx="145.7" cy="115.5" r=".83"/>
<circle cx="145.7" cy="119.7" r=".83"/>
<circle cx="145.7" cy="117.6" r=".83"/>
<circle cx="72.6" cy="157.5" r=".83"/>
<circle cx="72.6" cy="159.6" r=".83"/>
<circle cx="72.6" cy="161.8" r=".83"/>
<circle cx="72.6" cy="166" r=".83"/>
<circle cx="72.6" cy="163.9" r=".83"/>
<circle cx="72.6" cy="168.1" r=".83"/>
</g>
<g fill="none" stroke="#800000" stroke-width=".34">
<path d="M79.7 27.1h8.4v6.3h-8.4zM218.6 42.3h4.2M220.1 43.4h1.1M43.4 89.7h3.1v.5h-3.1zM43.9 88.1v1.1M46 88.1v1.1M40.2 104.9h9.5v8.4h-9.5zM138.6 113.3h10.5v8.5h-10.5zM68.1 155.4h6.3v14.8h-6.3z"/>
<circle cx="239.6" cy="94.4" r=".11"/>
<circle cx="239.6" cy="98.6" r=".11"/>
</g>
<g fill="#800000" stroke="#800000" stroke-width=".21">
<path d="M71.3 34.1l1.1 .2 1 .6-.1 .1-1.2-.6-.8-.1z" fill-rule="evenodd"/>
<path d="M69.2 34.8l.9-.5 1.2-.2v.3l-1.3 .2-.7 .4z" fill-rule="evenodd"/>
<path d="M60.7 34.1l1.2 .2 1 .6-.2 .1-1.1-.6-.9-.1z" fill-rule="evenodd"/>
<path d="M58.6 34.8l1-.5 1.1-.2v.3l-1.2 .2-.7 .4z" fill-rule="evenodd"/>
<path d="M168.1 23.6l1.1 .2 1 .5-.1 .2-1.2-.6-.8-.1z" fill-rule="evenodd"/>
<path d="M165.9 24.3l1-.5 1.2-.2v.2l-1.3 .3-.7 .4z" fill-rule="evenodd"/>
</g>
<g fill="#800000" stroke="#800000" stroke-width=".21">
<path d="M58.9 32.7l.7 .1z"/>
<path d="M59.2 32.4l.1 .7z"/>
<path d="M160.1 86.4h3.3v.4h-3.3z"/>
<path d="M160.1 87.3h3.3v.4h-3.3z"/>
<path d="M168.5 107.5h3.4v.4h-3.4z"/>
<path d="M168.5 108.3h3.4v.4h-3.4z"/>
<path d="M66.8 109.2h.7v4.1h-.7z"/>
<path d="M45.7 107.1h.6v4.2h-.6z"/>
</g>
<g fill="none" stroke="#008000" stroke-width=".21">
<path d="M163.9 18.7v14.7h10.5M220.7 18.7v2.1M227 18.7v4.2M35.6 25.7v.9l.4 .4 .4-.4v-.9M36.9 27h.5M36.9 25.7h.5M37.1 25.7v1.3M38.7 25.7v1.3l-.9-1.3v1.3M40.5 27h.9M40.5 26.1l.5-.4v1.3M41.9 25.9l.2-.2h.5l.2 .2v.2l-.9 .9h.9M43.2 25.7v.9l.5 .4 .4-.4v-.9"/>
<path d="M50.2 33.4h4.2v6.3h29.5v-4.2M50.2 29.2h27.4M60.7 29.2v2.1M60.7 37.6v2.1M71.3 29.2v2.1M71.3 37.6v2.1M79.8 23.6v1.3h.8M81.1 23.6h.9v.2l-.9 .9v.2M82.7 24.3l-.2 .2 .2 .4h.4l.3-.2-.3-.4M82.7 24.3l-.2-.3 .2-.4h.4l.3 .2-.3 .5M82.7 24.3h.4M84.7 23.8v.9l-.2 .2h-.5l-.2-.2"/>
<path d="M84.7 23.8l-.2-.2h-.5l-.2 .2v.9M84.7 23.8l-.9 .9M86.1 23.6h-.9v.7l.4-.3h.3l.2 .3v.4l-.2 .2h-.5l-.2-.2M87.4 23.8l-.2-.2h-.4l-.3 .2v.9l.3 .2h.4l.2-.2M87.9 23.6v.9l.4 .4 .5-.4v-.9M94.4 27.1v2.1h-4.2M157.5 35.5h16.9M159.6 31.3v4.2M168.1 20.8h-8.5v2.1M174.4 39.7h-4.2v8.4M205.9 35.5h14.8v2.1M205.9 37.6h6.4v10.5"/>
<path d="M205.9 39.7h6.4M205.9 33.4h23.2M205.9 31.3h16.9M212.3 34.1v.9l.5 .4 .4-.4v-.9M213.2 32.2l-.2-.2h-.5l-.2 .4 .2 .3h.5l.2 .4-.2 .2h-.5l-.2-.2M213.2 30.1l-.2-.2h-.5l-.2 .2 .2 .5h.5l.2 .2v.2l-.2 .2h-.5l-.2-.2M213.7 32h.7l.2 .2v.9l-.2 .2h-.7zM213.7 34.1h.7l.2 .2-.2 .5 .2 .4-.2 .2h-.7zM213.7 34.8h.7M214.6 30.1l-.2-.2h-.5l-.2 .2v.9l.2 .2h.5l.2-.2M215 32.7h.9M215 29.9v1.3h.9"/>
<path d="M215 33.3v-.9l.5-.4 .4 .4v.9M215 35.4v-.9l.5-.4 .4 .4v.9M215 34.8h.9M216.4 34.1h.9M216.8 34.1v1.3M220.7 29.2v2.1M227 31.3v2.1M170.2 41.8h4.2M170.2 43.9h4.2M170.2 46h4.2M205.9 41.8h6.4M205.9 43.9h6.4"/>
<path d="M205.9 46h6.4M220.7 46v2.1M170.2 67.1v2.1M170.2 77.6v2.1h4.2M239.6 79.7v2.1M35.5 92.3h8.4M35.5 90.2v4.2M46 92.3h8.4v14.7h-2.1M69.2 83.9v6.3M69.2 94.4v12.6M69.2 88.1h4.2M69.2 96.5h4.2"/>
<path d="M77.6 82.5v1.3h.9M79 83.8h.5M79 82.5h.5M79.2 82.5v1.3M80.8 82.7l-.2-.2h-.5l-.2 .2v.9l.2 .2h.5l.2-.2v-.4h-.5M81.3 83.2h.9M81.3 82.5v1.3M81.8 96.5v8.4h6.3M82.2 82.5v1.3M82.6 82.5h.9M83.1 82.5v1.3M83.9 96.5v4.2h4.2"/>
<path d="M86.2 82.7l-.2-.2h-.4l-.3 .4 .3 .3h.4l.2 .2v.2l-.2 .2h-.4l-.3-.2M86.7 82.5v1.3l.4-.4 .5 .4v-1.3M88 83.8h.5M88 82.5h.5M88.3 82.5v1.3M88.9 82.5h1M89.4 82.5v1.3M91.2 82.7l-.2-.2h-.5l-.2 .2v.9l.2 .2h.5l.2-.2M91.7 83.2h.9M91.7 82.5v1.3M92.6 82.5v1.3M94.4 83.4h.6l.3-.2v-.5l-.3-.2h-.6v1.3"/>
<path d="M94.8 83.4l.5 .4M95.7 83.2h.5M96.6 82.5h-.9v1.3h.9M97.1 82.5v1.3h.9M98.4 83.2h.9M98.4 83.8v-.9l.5-.4 .4 .4v.9M99.8 82.5v.2l.4 .5M100.2 83.2v.6M100.7 82.5v.2l-.5 .5M161.8 83.9h12.6M174.4 88.1h-4.2v4.2h-8.4v-2.1M214.4 88.1h8.4"/>
<path d="M214.4 90.2h8.4M214.4 98.6h8.4M239.6 90.2v2.1h-6.3v14.7h-18.9M29.2 111.3h8.4M35.5 102.8v4.2h2.1M52.3 111.3h2.1M62.8 111.3h2.2M69.2 115.5v2.1M130.2 119.7h6.3M130.2 115.5h6.3M130.2 117.6h6.3M151.2 119.7h6.3v2.1"/>
<path d="M151.2 115.5h6.3M151.2 117.6h6.3M170.2 104.9h4.2v2.1M174.4 109.2v2.1h-4.2M214.4 113.3h6.3M214.4 109.2h8.4M214.4 102.8h8.4M214.4 100.7h8.4M229.1 113.3h2.1M237.5 113.3h2.1M239.6 100.7v2.1M214.4 123.9h12.6"/>
<path d="M214.4 128.1h12.6M214.4 126h12.6M58.7 159.6h12.6M60.7 157.5h10.6M58.7 161.8h12.6M58.7 163.9h12.6M58.7 166h12.6M58.7 168.1h12.6"/>
</g>
<g fill="#008000" stroke="#008000" stroke-width=".21">
<circle cx="212.3" cy="39.7" r=".42"/>
<circle cx="212.3" cy="41.8" r=".42"/>
<circle cx="212.3" cy="43.9" r=".42"/>
<circle cx="212.3" cy="46" r=".42"/>
<circle cx="161.8" cy="83.9" r=".42"/>
<circle cx="174.4" cy="104.9" r=".42"/>
<circle cx="170.2" cy="104.9" r=".42"/>
<circle cx="71.3" cy="39.7" r=".42"/>
<circle cx="60.7" cy="39.7" r=".42"/>
<circle cx="83.9" cy="39.7" r=".42"/>
<circle cx="170.2" cy="46" r=".42"/>
<circle cx="170.2" cy="43.9" r=".42"/>
<circle cx="170.2" cy="41.8" r=".42"/>
<circle cx="69.2" cy="88.1" r=".42"/>
<circle cx="163.9" cy="20.8" r=".42"/>
<circle cx="166" cy="92.3" r=".42"/>
<circle cx="174.4" cy="111.3" r=".42"/>
<circle cx="170.2" cy="111.3" r=".42"/>
<circle cx="35.5" cy="92.3" r=".42"/>
<circle cx="227" cy="33.4" r=".42"/>
<circle cx="220.7" cy="31.3" r=".42"/>
<circle cx="71.3" cy="29.2" r=".42"/>
<circle cx="60.7" cy="29.2" r=".42"/>
<circle cx="69.2" cy="96.5" r=".42"/>
<circle cx="159.6" cy="35.5" r=".42"/>
<circle cx="239.6" cy="92.3" r=".42"/>
</g>
</svg>
